# BSD 3-Clause License
#
# Copyright (c) 2026 <Sungwoo Jung, Cheng-Yu Tsai, Amaan Rahman, Junsik Yoon, Sandra Maria Shaji, Sung Kyu Lim >, University of Southern California
#
# Redistribution and use in source and binary forms, with or without
# modification, are permitted under the BSD 3-Clause License.
# See the LICENSE file in the project root for full license terms.


VERSION 5.8 ;
BUSBITCHARS "[]" ;
DIVIDERCHAR "/" ;

UNITS
  DATABASE MICRONS 10000 ;
END UNITS

MANUFACTURINGGRID 0.0001 ;

PROPERTYDEFINITIONS
  MACRO snapMode STRING ;
  MACRO segSnapMode STRING ;
  MACRO dimmingIntensity INTEGER ;
  MACRO arrayDisplay STRING ;
  MACRO displayResolution STRING ;
  MACRO instanceDrawingMode STRING ;
  MACRO autoZoomScale INTEGER ;
  MACRO filterSizeDrawingStyle STRING ;
  MACRO dimmingScope STRING ;
  MACRO filterSize REAL ;
  MACRO scrollPercent INTEGER ;
  MACRO gridMultiple INTEGER ;
  MACRO gridSpacing REAL ;
  MACRO xSnapSpacing REAL ;
  MACRO instLabel STRING ;
  MACRO autoZoomMode STRING ;
  MACRO lppVisibilityMode STRING ;
  MACRO stopLevel INTEGER ;
  MACRO mergeScope STRING ;
  MACRO ySnapSpacing REAL ;
  MACRO startLevel INTEGER ;
  MACRO pathCL STRING ;
END PROPERTYDEFINITIONS

LAYER well
  TYPE MASTERSLICE ;
END well

LAYER Gate
  TYPE MASTERSLICE ;
END Gate

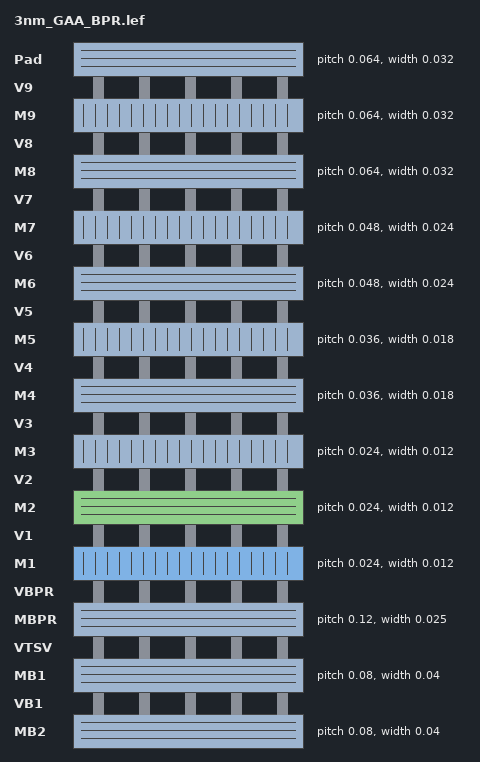
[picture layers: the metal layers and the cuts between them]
LAYER MB2
  TYPE ROUTING ;
  DIRECTION HORIZONTAL ;
  PITCH 0.08 ;
  WIDTH 0.04 ;
  PROPERTY LEF58_WIDTH "WIDTH 0.04 WRONGDIRECTION ;" ;
END MB2

LAYER VB1
  TYPE CUT ;
END VB1

LAYER MB1
  TYPE ROUTING ;
  DIRECTION HORIZONTAL ;
  PITCH 0.08 ;
  WIDTH 0.04 ;
  PROPERTY LEF58_WIDTH "WIDTH 0.04 WRONGDIRECTION ;" ;
END MB1

LAYER VTSV
  TYPE CUT ;
END VTSV

LAYER MBPR
  TYPE ROUTING ;
  DIRECTION HORIZONTAL ;
  PITCH 0.12 ;
  WIDTH 0.025 ;
  PROPERTY LEF58_WIDTH "WIDTH 0.025 WRONGDIRECTION ;" ;
END MBPR

LAYER VBPR
  TYPE CUT ;
END VBPR


LAYER M1
  TYPE ROUTING ;
  DIRECTION VERTICAL ;
  PITCH 0.024 ;
  WIDTH 0.012 ;
  PROPERTY LEF58_WIDTH "WIDTH 0.012 WRONGDIRECTION ;" ;
END M1

LAYER V1
  TYPE CUT ;
END V1

LAYER M2
  TYPE ROUTING ;
  DIRECTION HORIZONTAL ;
  PITCH 0.024 ;
  WIDTH 0.012 ;
  PROPERTY LEF58_WIDTH "WIDTH 0.012 WRONGDIRECTION ;" ;
END M2

LAYER V2
  TYPE CUT ;
END V2

LAYER M3
  TYPE ROUTING ;
  DIRECTION VERTICAL ;
  PITCH 0.024 ;
  WIDTH 0.012 ;
  PROPERTY LEF58_WIDTH "WIDTH 0.012 WRONGDIRECTION ;" ;
END M3

LAYER V3
  TYPE CUT ;
END V3

LAYER M4
  TYPE ROUTING ;
  DIRECTION HORIZONTAL ;
  PITCH 0.036 ;
  WIDTH 0.018 ;
  PROPERTY LEF58_WIDTH "WIDTH 0.018 WRONGDIRECTION ;" ;
END M4

LAYER V4
  TYPE CUT ;
END V4

LAYER M5
  TYPE ROUTING ;
  DIRECTION VERTICAL ;
  PITCH 0.036 ;
  WIDTH 0.018 ;
  PROPERTY LEF58_WIDTH "WIDTH 0.018 WRONGDIRECTION ;" ;
END M5

LAYER V5
  TYPE CUT ;
END V5

LAYER M6
  TYPE ROUTING ;
  DIRECTION HORIZONTAL ;
  PITCH 0.048 ;
  WIDTH 0.024 ;
  PROPERTY LEF58_WIDTH "WIDTH 0.024 WRONGDIRECTION ;" ;
END M6

LAYER V6
  TYPE CUT ;
END V6

LAYER M7
  TYPE ROUTING ;
  DIRECTION VERTICAL ;
  PITCH 0.048 ;
  WIDTH 0.024 ;
  PROPERTY LEF58_WIDTH "WIDTH 0.024 WRONGDIRECTION ;" ;
END M7

LAYER V7
  TYPE CUT ;
END V7

LAYER M8
  TYPE ROUTING ;
  DIRECTION HORIZONTAL ;
  PITCH 0.064 ;
  WIDTH 0.032 ;
  PROPERTY LEF58_WIDTH "WIDTH 0.032 WRONGDIRECTION ;" ;
END M8

LAYER V8
  TYPE CUT ;
END V8

LAYER M9
  TYPE ROUTING ;
  DIRECTION VERTICAL ;
  PITCH 0.064 ;
  WIDTH 0.032 ;
  PROPERTY LEF58_WIDTH "WIDTH 0.032 WRONGDIRECTION ;" ;
END M9

LAYER V9
  TYPE CUT ;
END V9

LAYER Pad
  TYPE ROUTING ;
  DIRECTION HORIZONTAL ;
  PITCH 0.064 ;
  WIDTH 0.032 ;
  PROPERTY LEF58_WIDTH "WIDTH 0.032 WRONGDIRECTION ;" ;
END Pad

LAYER Active
  TYPE MASTERSLICE ;
END Active

LAYER fin
  TYPE MASTERSLICE ;
END fin

LAYER P_SUB
  TYPE MASTERSLICE ;
END P_SUB

LAYER Dummy
  TYPE MASTERSLICE ;
END Dummy

LAYER GCut
  TYPE MASTERSLICE ;
END GCut

LAYER Nselect
  TYPE MASTERSLICE ;
END Nselect

LAYER Pselect
  TYPE MASTERSLICE ;
END Pselect

LAYER SDT
  TYPE MASTERSLICE ;
END SDT

LAYER LIG
  TYPE MASTERSLICE ;
END LIG

LAYER LISD
  TYPE MASTERSLICE ;
END LISD

LAYER V0
  TYPE MASTERSLICE ;
END V0

LAYER SLVT
  TYPE MASTERSLICE ;
END SLVT

LAYER LVT
  TYPE MASTERSLICE ;
END LVT

LAYER SRAMDRC
  TYPE MASTERSLICE ;
END SRAMDRC

LAYER BOUNDARY
  TYPE MASTERSLICE ;
END BOUNDARY

LAYER TEXT
  TYPE MASTERSLICE ;
END TEXT

LAYER SRAMVT
  TYPE MASTERSLICE ;
END SRAMVT

LAYER text
  TYPE MASTERSLICE ;
END text



#SITE coreSite
#  CLASS CORE ;
#  SIZE 0.042 BY 0.144 ;
#END core

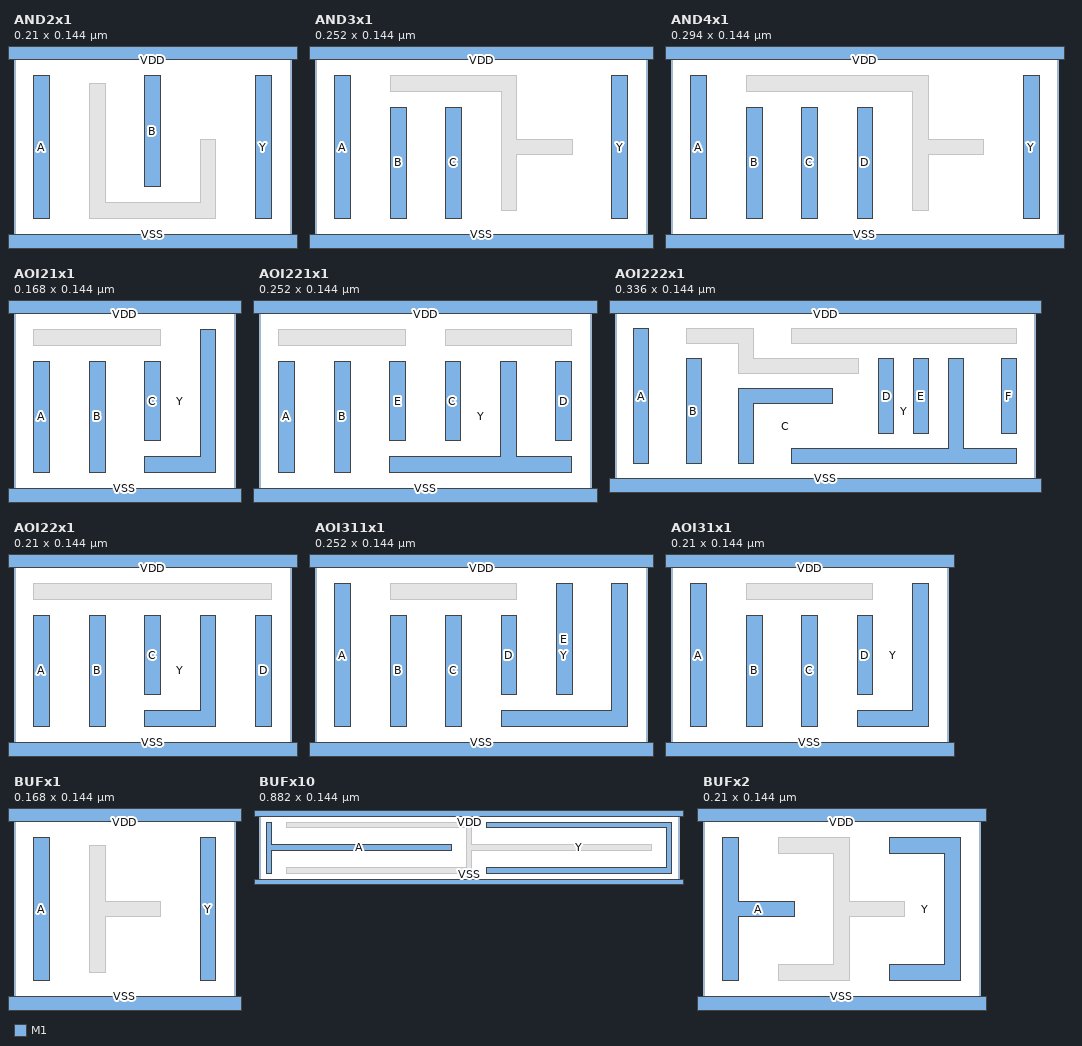
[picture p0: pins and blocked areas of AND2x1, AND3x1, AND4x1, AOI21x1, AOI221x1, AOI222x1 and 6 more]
MACRO AND2x1
  CLASS CORE ;
  FOREIGN AND2x1 ;
  ORIGIN 0 0 ;
  SIZE 0.21 BY 0.144 ;
  SYMMETRY X Y ;
  SITE coreSite ;
  PIN A
    DIRECTION INPUT ;
    USE SIGNAL ;
    PORT
      LAYER M1 ;
        RECT 0.0150 0.0180 0.0270 0.1260 ;
    END
  END A
  PIN B
    DIRECTION INPUT ;
    USE SIGNAL ;
    PORT
      LAYER M1 ;
        RECT 0.0990 0.0420 0.1110 0.1260 ;
    END
  END B
  PIN Y
    DIRECTION OUTPUT ;
    USE SIGNAL ;
    PORT
      LAYER M1 ;
        RECT 0.1830 0.0180 0.1950 0.1260 ;
    END
  END Y
  PIN VDD
    DIRECTION INOUT ;
    USE POWER ;
    PORT
      LAYER M1 ;
        RECT -0.0090 0.1380 0.2190 0.1500 ;
    END
  END VDD
  PIN VSS
    DIRECTION INOUT ;
    USE GROUND ;
    PORT
      LAYER M1 ;
        RECT -0.0090 -0.0060 0.2190 0.0060 ;
    END
  END VSS
  OBS
    LAYER M1 ;
      POLYGON 0.0690 0.1200 0.0690 0.0300 0.1410 0.0300 0.1410 0.0780 0.1530 0.0780 0.1530 0.0180 0.0570 0.0180 0.0570 0.1200 ;
  END
END AND2x1

MACRO AND3x1
  CLASS CORE ;
  FOREIGN AND3x1 ;
  ORIGIN 0 0 ;
  SIZE 0.252 BY 0.144 ;
  SYMMETRY X Y ;
  SITE coreSite ;
  PIN A
    DIRECTION INPUT ;
    USE SIGNAL ;
    PORT
      LAYER M1 ;
        RECT 0.0150 0.0180 0.0270 0.1260 ;
    END
  END A
  PIN B
    DIRECTION INPUT ;
    USE SIGNAL ;
    PORT
      LAYER M1 ;
        RECT 0.0570 0.0180 0.0690 0.1020 ;
    END
  END B
  PIN C
    DIRECTION INPUT ;
    USE SIGNAL ;
    PORT
      LAYER M1 ;
        RECT 0.0990 0.0180 0.1110 0.1020 ;
    END
  END C
  PIN Y
    DIRECTION OUTPUT ;
    USE SIGNAL ;
    PORT
      LAYER M1 ;
        RECT 0.2250 0.0180 0.2370 0.1260 ;
    END
  END Y
  PIN VDD
    DIRECTION INOUT ;
    USE POWER ;
    PORT
      LAYER M1 ;
        RECT -0.0090 0.1380 0.2610 0.1500 ;
    END
  END VDD
  PIN VSS
    DIRECTION INOUT ;
    USE GROUND ;
    PORT
      LAYER M1 ;
        RECT -0.0090 -0.0060 0.2610 0.0060 ;
    END
  END VSS
  OBS
    LAYER M1 ;
      POLYGON 0.1530 0.1260 0.1530 0.0780 0.1950 0.0780 0.1950 0.0660 0.1530 0.0660 0.1530 0.0240 0.1410 0.0240 0.1410 0.1140 0.0570 0.1140 0.0570 0.1260 ;
  END
END AND3x1

MACRO AND4x1
  CLASS CORE ;
  FOREIGN AND4x1 ;
  ORIGIN 0 0 ;
  SIZE 0.294 BY 0.144 ;
  SYMMETRY X Y ;
  SITE coreSite ;
  PIN A
    DIRECTION INPUT ;
    USE SIGNAL ;
    PORT
      LAYER M1 ;
        RECT 0.0150 0.0180 0.0270 0.1260 ;
    END
  END A
  PIN B
    DIRECTION INPUT ;
    USE SIGNAL ;
    PORT
      LAYER M1 ;
        RECT 0.0570 0.0180 0.0690 0.1020 ;
    END
  END B
  PIN C
    DIRECTION INPUT ;
    USE SIGNAL ;
    PORT
      LAYER M1 ;
        RECT 0.0990 0.0180 0.1110 0.1020 ;
    END
  END C
  PIN D
    DIRECTION INPUT ;
    USE SIGNAL ;
    PORT
      LAYER M1 ;
        RECT 0.1410 0.0180 0.1530 0.1020 ;
    END
  END D
  PIN Y
    DIRECTION OUTPUT ;
    USE SIGNAL ;
    PORT
      LAYER M1 ;
        RECT 0.2670 0.0180 0.2790 0.1260 ;
    END
  END Y
  PIN VDD
    DIRECTION INOUT ;
    USE POWER ;
    PORT
      LAYER M1 ;
        RECT -0.0090 0.1380 0.3030 0.1500 ;
    END
  END VDD
  PIN VSS
    DIRECTION INOUT ;
    USE GROUND ;
    PORT
      LAYER M1 ;
        RECT -0.0090 -0.0060 0.3030 0.0060 ;
    END
  END VSS
  OBS
    LAYER M1 ;
      POLYGON 0.1950 0.1260 0.1950 0.0780 0.2370 0.0780 0.2370 0.0660 0.1950 0.0660 0.1950 0.0240 0.1830 0.0240 0.1830 0.1140 0.0570 0.1140 0.0570 0.1260 ;
  END
END AND4x1

MACRO AOI21x1
  CLASS CORE ;
  FOREIGN AOI21x1 ;
  ORIGIN 0 0 ;
  SIZE 0.168 BY 0.144 ;
  SYMMETRY X Y ;
  SITE coreSite ;
  PIN A
    DIRECTION INPUT ;
    USE SIGNAL ;
    PORT
      LAYER M1 ;
        RECT 0.0150 0.0180 0.0270 0.1020 ;
    END
  END A
  PIN B
    DIRECTION INPUT ;
    USE SIGNAL ;
    PORT
      LAYER M1 ;
        RECT 0.0570 0.0180 0.0690 0.1020 ;
    END
  END B
  PIN C
    DIRECTION INPUT ;
    USE SIGNAL ;
    PORT
      LAYER M1 ;
        RECT 0.0990 0.0420 0.1110 0.1020 ;
    END
  END C
  PIN Y
    DIRECTION OUTPUT ;
    USE SIGNAL ;
    PORT
      LAYER M1 ;
        POLYGON 0.1530 0.1260 0.1530 0.0180 0.0990 0.0180 0.0990 0.0300 0.1410 0.0300 0.1410 0.1260 ;
    END
  END Y
  PIN VDD
    DIRECTION INOUT ;
    USE POWER ;
    PORT
      LAYER M1 ;
        RECT -0.0090 0.1380 0.1770 0.1500 ;
    END
  END VDD
  PIN VSS
    DIRECTION INOUT ;
    USE GROUND ;
    PORT
      LAYER M1 ;
        RECT -0.0090 -0.0060 0.1770 0.0060 ;
    END
  END VSS
  OBS
    LAYER M1 ;
      RECT 0.0150 0.1140 0.1110 0.1260 ;
  END
END AOI21x1

MACRO AOI221x1
  CLASS CORE ;
  FOREIGN AOI221x1 ;
  ORIGIN 0 0 ;
  SIZE 0.252 BY 0.144 ;
  SYMMETRY X Y ;
  SITE coreSite ;
  PIN A
    DIRECTION INPUT ;
    USE SIGNAL ;
    PORT
      LAYER M1 ;
        RECT 0.0150 0.0180 0.0270 0.1020 ;
    END
  END A
  PIN B
    DIRECTION INPUT ;
    USE SIGNAL ;
    PORT
      LAYER M1 ;
        RECT 0.0570 0.0180 0.0690 0.1020 ;
    END
  END B
  PIN C
    DIRECTION INPUT ;
    USE SIGNAL ;
    PORT
      LAYER M1 ;
        RECT 0.1410 0.0420 0.1530 0.1020 ;
    END
  END C
  PIN D
    DIRECTION INPUT ;
    USE SIGNAL ;
    PORT
      LAYER M1 ;
        RECT 0.2250 0.0420 0.2370 0.1020 ;
    END
  END D
  PIN E
    DIRECTION INPUT ;
    USE SIGNAL ;
    PORT
      LAYER M1 ;
        RECT 0.0990 0.0420 0.1110 0.1020 ;
    END
  END E
  PIN Y
    DIRECTION OUTPUT ;
    USE SIGNAL ;
    PORT
      LAYER M1 ;
        POLYGON 0.1950 0.1020 0.1950 0.0300 0.2370 0.0300 0.2370 0.0180 0.0990 0.0180 0.0990 0.0300 0.1830 0.0300 0.1830 0.1020 ;
    END
  END Y
  PIN VDD
    DIRECTION INOUT ;
    USE POWER ;
    PORT
      LAYER M1 ;
        RECT -0.0090 0.1380 0.2610 0.1500 ;
    END
  END VDD
  PIN VSS
    DIRECTION INOUT ;
    USE GROUND ;
    PORT
      LAYER M1 ;
        RECT -0.0090 -0.0060 0.2610 0.0060 ;
    END
  END VSS
  OBS
    LAYER M1 ;
      RECT 0.1410 0.1140 0.2370 0.1260 ;
      RECT 0.0150 0.1140 0.1110 0.1260 ;
  END
END AOI221x1

MACRO AOI222x1
  CLASS CORE ;
  FOREIGN AOI222x1 ;
  ORIGIN 0 0 ;
  SIZE 0.336 BY 0.144 ;
  SYMMETRY X Y ;
  SITE coreSite ;
  PIN A
    DIRECTION INPUT ;
    USE SIGNAL ;
    PORT
      LAYER M1 ;
        RECT 0.0150 0.0180 0.0270 0.1260 ;
    END
  END A
  PIN B
    DIRECTION INPUT ;
    USE SIGNAL ;
    PORT
      LAYER M1 ;
        RECT 0.0570 0.0180 0.0690 0.1020 ;
    END
  END B
  PIN C
    DIRECTION INPUT ;
    USE SIGNAL ;
    PORT
      LAYER M1 ;
        POLYGON 0.1740 0.0780 0.1740 0.0660 0.1110 0.0660 0.1110 0.0180 0.0990 0.0180 0.0990 0.0780 ;
    END
  END C
  PIN D
    DIRECTION INPUT ;
    USE SIGNAL ;
    PORT
      LAYER M1 ;
        RECT 0.2110 0.0420 0.2230 0.1020 ;
    END
  END D
  PIN E
    DIRECTION INPUT ;
    USE SIGNAL ;
    PORT
      LAYER M1 ;
        RECT 0.2390 0.0420 0.2510 0.1020 ;
    END
  END E
  PIN F
    DIRECTION INPUT ;
    USE SIGNAL ;
    PORT
      LAYER M1 ;
        RECT 0.3090 0.0420 0.3210 0.1020 ;
    END
  END F
  PIN Y
    DIRECTION OUTPUT ;
    USE SIGNAL ;
    PORT
      LAYER M1 ;
        POLYGON 0.2790 0.1020 0.2790 0.0300 0.3210 0.0300 0.3210 0.0180 0.1410 0.0180 0.1410 0.0300 0.2670 0.0300 0.2670 0.1020 ;
    END
  END Y
  PIN VDD
    DIRECTION INOUT ;
    USE POWER ;
    PORT
      LAYER M1 ;
        RECT -0.0090 0.1380 0.3450 0.1500 ;
    END
  END VDD
  PIN VSS
    DIRECTION INOUT ;
    USE GROUND ;
    PORT
      LAYER M1 ;
        RECT -0.0090 -0.0060 0.3450 0.0060 ;
    END
  END VSS
  OBS
    LAYER M1 ;
      RECT 0.1410 0.1140 0.3210 0.1260 ;
      POLYGON 0.1110 0.1260 0.1110 0.1020 0.1950 0.1020 0.1950 0.0900 0.0990 0.0900 0.0990 0.1140 0.0570 0.1140 0.0570 0.1260 ;
  END
END AOI222x1

MACRO AOI22x1
  CLASS CORE ;
  FOREIGN AOI22x1 ;
  ORIGIN 0 0 ;
  SIZE 0.21 BY 0.144 ;
  SYMMETRY X Y ;
  SITE coreSite ;
  PIN A
    DIRECTION INPUT ;
    USE SIGNAL ;
    PORT
      LAYER M1 ;
        RECT 0.0150 0.0180 0.0270 0.1020 ;
    END
  END A
  PIN B
    DIRECTION INPUT ;
    USE SIGNAL ;
    PORT
      LAYER M1 ;
        RECT 0.0570 0.0180 0.0690 0.1020 ;
    END
  END B
  PIN C
    DIRECTION INPUT ;
    USE SIGNAL ;
    PORT
      LAYER M1 ;
        RECT 0.0990 0.0420 0.1110 0.1020 ;
    END
  END C
  PIN D
    DIRECTION INPUT ;
    USE SIGNAL ;
    PORT
      LAYER M1 ;
        RECT 0.1830 0.0180 0.1950 0.1020 ;
    END
  END D
  PIN Y
    DIRECTION OUTPUT ;
    USE SIGNAL ;
    PORT
      LAYER M1 ;
        POLYGON 0.1530 0.1020 0.1530 0.0180 0.0990 0.0180 0.0990 0.0300 0.1410 0.0300 0.1410 0.1020 ;
    END
  END Y
  PIN VDD
    DIRECTION INOUT ;
    USE POWER ;
    PORT
      LAYER M1 ;
        RECT -0.0090 0.1380 0.2190 0.1500 ;
    END
  END VDD
  PIN VSS
    DIRECTION INOUT ;
    USE GROUND ;
    PORT
      LAYER M1 ;
        RECT -0.0090 -0.0060 0.2190 0.0060 ;
    END
  END VSS
  OBS
    LAYER M1 ;
      RECT 0.0150 0.1140 0.1950 0.1260 ;
  END
END AOI22x1

MACRO AOI311x1
  CLASS CORE ;
  FOREIGN AOI311x1 ;
  ORIGIN 0 0 ;
  SIZE 0.252 BY 0.144 ;
  SYMMETRY X Y ;
  SITE coreSite ;
  PIN A
    DIRECTION INPUT ;
    USE SIGNAL ;
    PORT
      LAYER M1 ;
        RECT 0.0150 0.0180 0.0270 0.1260 ;
    END
  END A
  PIN B
    DIRECTION INPUT ;
    USE SIGNAL ;
    PORT
      LAYER M1 ;
        RECT 0.0570 0.0180 0.0690 0.1020 ;
    END
  END B
  PIN C
    DIRECTION INPUT ;
    USE SIGNAL ;
    PORT
      LAYER M1 ;
        RECT 0.0990 0.0180 0.1110 0.1020 ;
    END
  END C
  PIN D
    DIRECTION INPUT ;
    USE SIGNAL ;
    PORT
      LAYER M1 ;
        RECT 0.1410 0.0420 0.1530 0.1020 ;
    END
  END D
  PIN E
    DIRECTION INPUT ;
    USE SIGNAL ;
    PORT
      LAYER M1 ;
        RECT 0.1830 0.0420 0.1950 0.1260 ;
    END
  END E
  PIN Y
    DIRECTION OUTPUT ;
    USE SIGNAL ;
    PORT
      LAYER M1 ;
        POLYGON 0.2370 0.1260 0.2370 0.0180 0.1410 0.0180 0.1410 0.0300 0.2250 0.0300 0.2250 0.1260 ;
    END
  END Y
  PIN VDD
    DIRECTION INOUT ;
    USE POWER ;
    PORT
      LAYER M1 ;
        RECT -0.0090 0.1380 0.2610 0.1500 ;
    END
  END VDD
  PIN VSS
    DIRECTION INOUT ;
    USE GROUND ;
    PORT
      LAYER M1 ;
        RECT -0.0090 -0.0060 0.2610 0.0060 ;
    END
  END VSS
  OBS
    LAYER M1 ;
      RECT 0.0570 0.1140 0.1530 0.1260 ;
  END
END AOI311x1

MACRO AOI31x1
  CLASS CORE ;
  FOREIGN AOI31x1 ;
  ORIGIN 0 0 ;
  SIZE 0.21 BY 0.144 ;
  SYMMETRY X Y ;
  SITE coreSite ;
  PIN A
    DIRECTION INPUT ;
    USE SIGNAL ;
    PORT
      LAYER M1 ;
        RECT 0.0150 0.0180 0.0270 0.1260 ;
    END
  END A
  PIN B
    DIRECTION INPUT ;
    USE SIGNAL ;
    PORT
      LAYER M1 ;
        RECT 0.0570 0.0180 0.0690 0.1020 ;
    END
  END B
  PIN C
    DIRECTION INPUT ;
    USE SIGNAL ;
    PORT
      LAYER M1 ;
        RECT 0.0990 0.0180 0.1110 0.1020 ;
    END
  END C
  PIN D
    DIRECTION INPUT ;
    USE SIGNAL ;
    PORT
      LAYER M1 ;
        RECT 0.1410 0.0420 0.1530 0.1020 ;
    END
  END D
  PIN Y
    DIRECTION OUTPUT ;
    USE SIGNAL ;
    PORT
      LAYER M1 ;
        POLYGON 0.1950 0.1260 0.1950 0.0180 0.1410 0.0180 0.1410 0.0300 0.1830 0.0300 0.1830 0.1260 ;
    END
  END Y
  PIN VDD
    DIRECTION INOUT ;
    USE POWER ;
    PORT
      LAYER M1 ;
        RECT -0.0090 0.1380 0.2190 0.1500 ;
    END
  END VDD
  PIN VSS
    DIRECTION INOUT ;
    USE GROUND ;
    PORT
      LAYER M1 ;
        RECT -0.0090 -0.0060 0.2190 0.0060 ;
    END
  END VSS
  OBS
    LAYER M1 ;
      RECT 0.0570 0.1140 0.1530 0.1260 ;
  END
END AOI31x1

MACRO BUFx1
  CLASS CORE ;
  FOREIGN BUFx1 ;
  ORIGIN 0 0 ;
  SIZE 0.168 BY 0.144 ;
  SYMMETRY X Y ;
  SITE coreSite ;
  PIN A
    DIRECTION INPUT ;
    USE SIGNAL ;
    PORT
      LAYER M1 ;
        RECT 0.0150 0.0180 0.0270 0.1260 ;
    END
  END A
  PIN Y
    DIRECTION OUTPUT ;
    USE SIGNAL ;
    PORT
      LAYER M1 ;
        RECT 0.1410 0.0180 0.1530 0.1260 ;
    END
  END Y
  PIN VDD
    DIRECTION INOUT ;
    USE POWER ;
    PORT
      LAYER M1 ;
        RECT -0.0090 0.1380 0.1770 0.1500 ;
    END
  END VDD
  PIN VSS
    DIRECTION INOUT ;
    USE GROUND ;
    PORT
      LAYER M1 ;
        RECT -0.0090 -0.0060 0.1770 0.0060 ;
    END
  END VSS
  OBS
    LAYER M1 ;
      POLYGON 0.0690 0.1200 0.0690 0.0780 0.1110 0.0780 0.1110 0.0660 0.0690 0.0660 0.0690 0.0240 0.0570 0.0240 0.0570 0.1200 ;
  END
END BUFx1

MACRO BUFx10
  CLASS CORE ;
  FOREIGN BUFx10 ;
  ORIGIN 0 0 ;
  SIZE 0.882 BY 0.144 ;
  SYMMETRY X Y ;
  SITE coreSite ;
  PIN A
    DIRECTION INPUT ;
    USE SIGNAL ;
    PORT
      LAYER M1 ;
        POLYGON 0.0270 0.1260 0.0270 0.0780 0.4050 0.0780 0.4050 0.0660 0.0270 0.0660 0.0270 0.0180 0.0150 0.0180 0.0150 0.1260 ;
    END
  END A
  PIN Y
    DIRECTION OUTPUT ;
    USE SIGNAL ;
    PORT
      LAYER M1 ;
        POLYGON 0.8670 0.1260 0.8670 0.0180 0.4770 0.0180 0.4770 0.0300 0.8550 0.0300 0.8550 0.1140 0.4770 0.1140 0.4770 0.1260 ;
    END
  END Y
  PIN VDD
    DIRECTION INOUT ;
    USE POWER ;
    PORT
      LAYER M1 ;
        RECT -0.0090 0.1380 0.8910 0.1500 ;
    END
  END VDD
  PIN VSS
    DIRECTION INOUT ;
    USE GROUND ;
    PORT
      LAYER M1 ;
        RECT -0.0090 -0.0060 0.8910 0.0060 ;
    END
  END VSS
  OBS
    LAYER M1 ;
      POLYGON 0.4470 0.1260 0.4470 0.0780 0.8250 0.0780 0.8250 0.0660 0.4470 0.0660 0.4470 0.0180 0.0570 0.0180 0.0570 0.0300 0.4350 0.0300 0.4350 0.1140 0.0570 0.1140 0.0570 0.1260 ;
  END
  PROPERTY stopLevel 0 ;
  PROPERTY startLevel 0 ;
  PROPERTY snapMode "orthogonal" ;
  PROPERTY segSnapMode "orthogonal" ;
  PROPERTY pathCL "yes" ;
  PROPERTY lppVisibilityMode "donotCheckValidity" ;
  PROPERTY instanceDrawingMode "BBox" ;
  PROPERTY autoZoomScale 90 ;
  PROPERTY gridSpacing 1 ;
  PROPERTY xSnapSpacing 0.001 ;
  PROPERTY autoZoomMode "Pan" ;
  PROPERTY mergeScope "pcells" ;
  PROPERTY gridMultiple 5 ;
  PROPERTY arrayDisplay "Full" ;
  PROPERTY scrollPercent 25 ;
  PROPERTY displayResolution "Medium" ;
  PROPERTY instLabel "master" ;
  PROPERTY ySnapSpacing 0.001 ;
  PROPERTY filterSize 6 ;
  PROPERTY dimmingIntensity 50 ;
  PROPERTY filterSizeDrawingStyle "empty" ;
  PROPERTY dimmingScope "none" ;
END BUFx10

MACRO BUFx2
  CLASS CORE ;
  FOREIGN BUFx2 ;
  ORIGIN 0 0 ;
  SIZE 0.21 BY 0.144 ;
  SYMMETRY X Y ;
  SITE coreSite ;
  PIN A
    DIRECTION INPUT ;
    USE SIGNAL ;
    PORT
      LAYER M1 ;
        POLYGON 0.0270 0.1260 0.0270 0.0780 0.0690 0.0780 0.0690 0.0660 0.0270 0.0660 0.0270 0.0180 0.0150 0.0180 0.0150 0.1260 ;
    END
  END A
  PIN Y
    DIRECTION OUTPUT ;
    USE SIGNAL ;
    PORT
      LAYER M1 ;
        POLYGON 0.1950 0.1260 0.1950 0.0180 0.1410 0.0180 0.1410 0.0300 0.1830 0.0300 0.1830 0.1140 0.1410 0.1140 0.1410 0.1260 ;
    END
  END Y
  PIN VDD
    DIRECTION INOUT ;
    USE POWER ;
    PORT
      LAYER M1 ;
        RECT -0.0090 0.1380 0.2190 0.1500 ;
    END
  END VDD
  PIN VSS
    DIRECTION INOUT ;
    USE GROUND ;
    PORT
      LAYER M1 ;
        RECT -0.0090 -0.0060 0.2190 0.0060 ;
    END
  END VSS
  OBS
    LAYER M1 ;
      POLYGON 0.1110 0.1260 0.1110 0.0780 0.1530 0.0780 0.1530 0.0660 0.1110 0.0660 0.1110 0.0180 0.0570 0.0180 0.0570 0.0300 0.0990 0.0300 0.0990 0.1140 0.0570 0.1140 0.0570 0.1260 ;
  END
END BUFx2

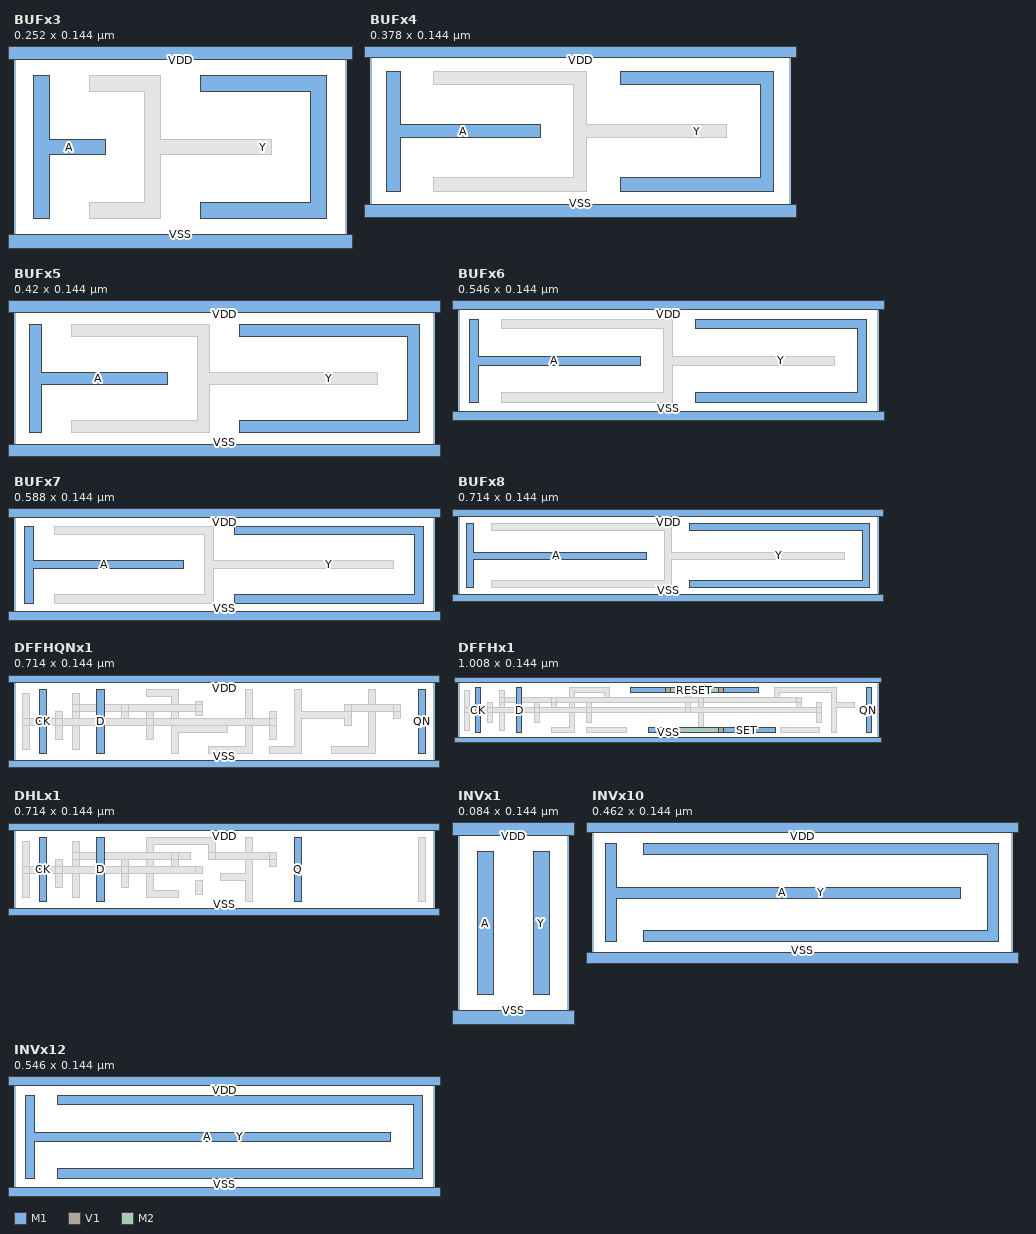
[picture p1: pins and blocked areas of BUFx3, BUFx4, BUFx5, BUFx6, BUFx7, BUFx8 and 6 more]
MACRO BUFx3
  CLASS CORE ;
  FOREIGN BUFx3 ;
  ORIGIN 0 0 ;
  SIZE 0.252 BY 0.144 ;
  SYMMETRY X Y ;
  SITE coreSite ;
  PIN A
    DIRECTION INPUT ;
    USE SIGNAL ;
    PORT
      LAYER M1 ;
        POLYGON 0.0270 0.1260 0.0270 0.0780 0.0690 0.0780 0.0690 0.0660 0.0270 0.0660 0.0270 0.0180 0.0150 0.0180 0.0150 0.1260 ;
    END
  END A
  PIN Y
    DIRECTION OUTPUT ;
    USE SIGNAL ;
    PORT
      LAYER M1 ;
        POLYGON 0.2370 0.1260 0.2370 0.0180 0.1410 0.0180 0.1410 0.0300 0.2250 0.0300 0.2250 0.1140 0.1410 0.1140 0.1410 0.1260 ;
    END
  END Y
  PIN VDD
    DIRECTION INOUT ;
    USE POWER ;
    PORT
      LAYER M1 ;
        RECT -0.0090 0.1380 0.2610 0.1500 ;
    END
  END VDD
  PIN VSS
    DIRECTION INOUT ;
    USE GROUND ;
    PORT
      LAYER M1 ;
        RECT -0.0090 -0.0060 0.2610 0.0060 ;
    END
  END VSS
  OBS
    LAYER M1 ;
      POLYGON 0.1110 0.1260 0.1110 0.0780 0.1950 0.0780 0.1950 0.0660 0.1110 0.0660 0.1110 0.0180 0.0570 0.0180 0.0570 0.0300 0.0990 0.0300 0.0990 0.1140 0.0570 0.1140 0.0570 0.1260 ;
  END
  PROPERTY stopLevel 0 ;
  PROPERTY startLevel 0 ;
  PROPERTY snapMode "orthogonal" ;
  PROPERTY segSnapMode "orthogonal" ;
  PROPERTY pathCL "yes" ;
  PROPERTY lppVisibilityMode "donotCheckValidity" ;
  PROPERTY instanceDrawingMode "BBox" ;
  PROPERTY autoZoomScale 90 ;
  PROPERTY gridSpacing 1 ;
  PROPERTY xSnapSpacing 0.001 ;
  PROPERTY autoZoomMode "Pan" ;
  PROPERTY mergeScope "pcells" ;
  PROPERTY gridMultiple 5 ;
  PROPERTY arrayDisplay "Full" ;
  PROPERTY scrollPercent 25 ;
  PROPERTY displayResolution "Medium" ;
  PROPERTY instLabel "master" ;
  PROPERTY ySnapSpacing 0.001 ;
  PROPERTY filterSize 6 ;
  PROPERTY dimmingIntensity 50 ;
  PROPERTY filterSizeDrawingStyle "empty" ;
  PROPERTY dimmingScope "none" ;
END BUFx3

MACRO BUFx4
  CLASS CORE ;
  FOREIGN BUFx4 ;
  ORIGIN 0 0 ;
  SIZE 0.378 BY 0.144 ;
  SYMMETRY X Y ;
  SITE coreSite ;
  PIN A
    DIRECTION INPUT ;
    USE SIGNAL ;
    PORT
      LAYER M1 ;
        POLYGON 0.0270 0.1260 0.0270 0.0780 0.1530 0.0780 0.1530 0.0660 0.0270 0.0660 0.0270 0.0180 0.0150 0.0180 0.0150 0.1260 ;
    END
  END A
  PIN Y
    DIRECTION OUTPUT ;
    USE SIGNAL ;
    PORT
      LAYER M1 ;
        POLYGON 0.3630 0.1260 0.3630 0.0180 0.2250 0.0180 0.2250 0.0300 0.3510 0.0300 0.3510 0.1140 0.2250 0.1140 0.2250 0.1260 ;
    END
  END Y
  PIN VDD
    DIRECTION INOUT ;
    USE POWER ;
    PORT
      LAYER M1 ;
        RECT -0.0090 0.1380 0.3870 0.1500 ;
    END
  END VDD
  PIN VSS
    DIRECTION INOUT ;
    USE GROUND ;
    PORT
      LAYER M1 ;
        RECT -0.0090 -0.0060 0.3870 0.0060 ;
    END
  END VSS
  OBS
    LAYER M1 ;
      POLYGON 0.1950 0.1260 0.1950 0.0780 0.3210 0.0780 0.3210 0.0660 0.1950 0.0660 0.1950 0.0180 0.0570 0.0180 0.0570 0.0300 0.1830 0.0300 0.1830 0.1140 0.0570 0.1140 0.0570 0.1260 ;
  END
  PROPERTY stopLevel 0 ;
  PROPERTY startLevel 0 ;
  PROPERTY snapMode "orthogonal" ;
  PROPERTY segSnapMode "orthogonal" ;
  PROPERTY pathCL "yes" ;
  PROPERTY lppVisibilityMode "donotCheckValidity" ;
  PROPERTY instanceDrawingMode "BBox" ;
  PROPERTY autoZoomScale 90 ;
  PROPERTY gridSpacing 1 ;
  PROPERTY xSnapSpacing 0.001 ;
  PROPERTY autoZoomMode "Pan" ;
  PROPERTY mergeScope "pcells" ;
  PROPERTY gridMultiple 5 ;
  PROPERTY arrayDisplay "Full" ;
  PROPERTY scrollPercent 25 ;
  PROPERTY displayResolution "Medium" ;
  PROPERTY instLabel "master" ;
  PROPERTY ySnapSpacing 0.001 ;
  PROPERTY filterSize 6 ;
  PROPERTY dimmingIntensity 50 ;
  PROPERTY filterSizeDrawingStyle "empty" ;
  PROPERTY dimmingScope "none" ;
END BUFx4

MACRO BUFx5
  CLASS CORE ;
  FOREIGN BUFx5 ;
  ORIGIN 0 0 ;
  SIZE 0.42 BY 0.144 ;
  SYMMETRY X Y ;
  SITE coreSite ;
  PIN A
    DIRECTION INPUT ;
    USE SIGNAL ;
    PORT
      LAYER M1 ;
        POLYGON 0.0270 0.1260 0.0270 0.0780 0.1530 0.0780 0.1530 0.0660 0.0270 0.0660 0.0270 0.0180 0.0150 0.0180 0.0150 0.1260 ;
    END
  END A
  PIN Y
    DIRECTION OUTPUT ;
    USE SIGNAL ;
    PORT
      LAYER M1 ;
        POLYGON 0.4050 0.1260 0.4050 0.0180 0.2250 0.0180 0.2250 0.0300 0.3930 0.0300 0.3930 0.1140 0.2250 0.1140 0.2250 0.1260 ;
    END
  END Y
  PIN VDD
    DIRECTION INOUT ;
    USE POWER ;
    PORT
      LAYER M1 ;
        RECT -0.0090 0.1380 0.4290 0.1500 ;
    END
  END VDD
  PIN VSS
    DIRECTION INOUT ;
    USE GROUND ;
    PORT
      LAYER M1 ;
        RECT -0.0090 -0.0060 0.4290 0.0060 ;
    END
  END VSS
  OBS
    LAYER M1 ;
      POLYGON 0.1950 0.1260 0.1950 0.0780 0.3630 0.0780 0.3630 0.0660 0.1950 0.0660 0.1950 0.0180 0.0570 0.0180 0.0570 0.0300 0.1830 0.0300 0.1830 0.1140 0.0570 0.1140 0.0570 0.1260 ;
  END
  PROPERTY stopLevel 0 ;
  PROPERTY startLevel 0 ;
  PROPERTY snapMode "orthogonal" ;
  PROPERTY segSnapMode "orthogonal" ;
  PROPERTY pathCL "yes" ;
  PROPERTY lppVisibilityMode "donotCheckValidity" ;
  PROPERTY instanceDrawingMode "BBox" ;
  PROPERTY autoZoomScale 90 ;
  PROPERTY gridSpacing 1 ;
  PROPERTY xSnapSpacing 0.001 ;
  PROPERTY autoZoomMode "Pan" ;
  PROPERTY mergeScope "pcells" ;
  PROPERTY gridMultiple 5 ;
  PROPERTY arrayDisplay "Full" ;
  PROPERTY scrollPercent 25 ;
  PROPERTY displayResolution "Medium" ;
  PROPERTY instLabel "master" ;
  PROPERTY ySnapSpacing 0.001 ;
  PROPERTY filterSize 6 ;
  PROPERTY dimmingIntensity 50 ;
  PROPERTY filterSizeDrawingStyle "empty" ;
  PROPERTY dimmingScope "none" ;
END BUFx5

MACRO BUFx6
  CLASS CORE ;
  FOREIGN BUFx6 ;
  ORIGIN 0 0 ;
  SIZE 0.546 BY 0.144 ;
  SYMMETRY X Y ;
  SITE coreSite ;
  PIN A
    DIRECTION INPUT ;
    USE SIGNAL ;
    PORT
      LAYER M1 ;
        POLYGON 0.0270 0.1260 0.0270 0.0780 0.2370 0.0780 0.2370 0.0660 0.0270 0.0660 0.0270 0.0180 0.0150 0.0180 0.0150 0.1260 ;
    END
  END A
  PIN Y
    DIRECTION OUTPUT ;
    USE SIGNAL ;
    PORT
      LAYER M1 ;
        POLYGON 0.5310 0.1260 0.5310 0.0180 0.3090 0.0180 0.3090 0.0300 0.5190 0.0300 0.5190 0.1140 0.3090 0.1140 0.3090 0.1260 ;
    END
  END Y
  PIN VDD
    DIRECTION INOUT ;
    USE POWER ;
    PORT
      LAYER M1 ;
        RECT -0.0090 0.1380 0.5550 0.1500 ;
    END
  END VDD
  PIN VSS
    DIRECTION INOUT ;
    USE GROUND ;
    PORT
      LAYER M1 ;
        RECT -0.0090 -0.0060 0.5550 0.0060 ;
    END
  END VSS
  OBS
    LAYER M1 ;
      POLYGON 0.2790 0.1260 0.2790 0.0780 0.4890 0.0780 0.4890 0.0660 0.2790 0.0660 0.2790 0.0180 0.0570 0.0180 0.0570 0.0300 0.2670 0.0300 0.2670 0.1140 0.0570 0.1140 0.0570 0.1260 ;
  END
  PROPERTY stopLevel 0 ;
  PROPERTY startLevel 0 ;
  PROPERTY snapMode "orthogonal" ;
  PROPERTY segSnapMode "orthogonal" ;
  PROPERTY pathCL "yes" ;
  PROPERTY lppVisibilityMode "donotCheckValidity" ;
  PROPERTY instanceDrawingMode "BBox" ;
  PROPERTY autoZoomScale 90 ;
  PROPERTY gridSpacing 1 ;
  PROPERTY xSnapSpacing 0.001 ;
  PROPERTY autoZoomMode "Pan" ;
  PROPERTY mergeScope "pcells" ;
  PROPERTY gridMultiple 5 ;
  PROPERTY arrayDisplay "Full" ;
  PROPERTY scrollPercent 25 ;
  PROPERTY displayResolution "Medium" ;
  PROPERTY instLabel "master" ;
  PROPERTY ySnapSpacing 0.001 ;
  PROPERTY filterSize 6 ;
  PROPERTY dimmingIntensity 50 ;
  PROPERTY filterSizeDrawingStyle "empty" ;
  PROPERTY dimmingScope "none" ;
END BUFx6

MACRO BUFx7
  CLASS CORE ;
  FOREIGN BUFx7 ;
  ORIGIN 0 0 ;
  SIZE 0.588 BY 0.144 ;
  SYMMETRY X Y ;
  SITE coreSite ;
  PIN A
    DIRECTION INPUT ;
    USE SIGNAL ;
    PORT
      LAYER M1 ;
        POLYGON 0.0270 0.1260 0.0270 0.0780 0.2370 0.0780 0.2370 0.0660 0.0270 0.0660 0.0270 0.0180 0.0150 0.0180 0.0150 0.1260 ;
    END
  END A
  PIN Y
    DIRECTION OUTPUT ;
    USE SIGNAL ;
    PORT
      LAYER M1 ;
        POLYGON 0.5730 0.1260 0.5730 0.0180 0.3090 0.0180 0.3090 0.0300 0.5610 0.0300 0.5610 0.1140 0.3090 0.1140 0.3090 0.1260 ;
    END
  END Y
  PIN VDD
    DIRECTION INOUT ;
    USE POWER ;
    PORT
      LAYER M1 ;
        RECT -0.0090 0.1380 0.5970 0.1500 ;
    END
  END VDD
  PIN VSS
    DIRECTION INOUT ;
    USE GROUND ;
    PORT
      LAYER M1 ;
        RECT -0.0090 -0.0060 0.5970 0.0060 ;
    END
  END VSS
  OBS
    LAYER M1 ;
      POLYGON 0.2790 0.1260 0.2790 0.0780 0.5310 0.0780 0.5310 0.0660 0.2790 0.0660 0.2790 0.0180 0.0570 0.0180 0.0570 0.0300 0.2670 0.0300 0.2670 0.1140 0.0570 0.1140 0.0570 0.1260 ;
  END
  PROPERTY stopLevel 0 ;
  PROPERTY startLevel 0 ;
  PROPERTY snapMode "orthogonal" ;
  PROPERTY segSnapMode "orthogonal" ;
  PROPERTY pathCL "yes" ;
  PROPERTY lppVisibilityMode "donotCheckValidity" ;
  PROPERTY instanceDrawingMode "BBox" ;
  PROPERTY autoZoomScale 90 ;
  PROPERTY gridSpacing 1 ;
  PROPERTY xSnapSpacing 0.001 ;
  PROPERTY autoZoomMode "Pan" ;
  PROPERTY mergeScope "pcells" ;
  PROPERTY gridMultiple 5 ;
  PROPERTY arrayDisplay "Full" ;
  PROPERTY scrollPercent 25 ;
  PROPERTY displayResolution "Medium" ;
  PROPERTY instLabel "master" ;
  PROPERTY ySnapSpacing 0.001 ;
  PROPERTY filterSize 6 ;
  PROPERTY dimmingIntensity 50 ;
  PROPERTY filterSizeDrawingStyle "empty" ;
  PROPERTY dimmingScope "none" ;
END BUFx7

MACRO BUFx8
  CLASS CORE ;
  FOREIGN BUFx8 ;
  ORIGIN 0 0 ;
  SIZE 0.714 BY 0.144 ;
  SYMMETRY X Y ;
  SITE coreSite ;
  PIN A
    DIRECTION INPUT ;
    USE SIGNAL ;
    PORT
      LAYER M1 ;
        POLYGON 0.0270 0.1260 0.0270 0.0780 0.3210 0.0780 0.3210 0.0660 0.0270 0.0660 0.0270 0.0180 0.0150 0.0180 0.0150 0.1260 ;
    END
  END A
  PIN Y
    DIRECTION OUTPUT ;
    USE SIGNAL ;
    PORT
      LAYER M1 ;
        POLYGON 0.6990 0.1260 0.6990 0.0180 0.3930 0.0180 0.3930 0.0300 0.6870 0.0300 0.6870 0.1140 0.3930 0.1140 0.3930 0.1260 ;
    END
  END Y
  PIN VDD
    DIRECTION INOUT ;
    USE POWER ;
    PORT
      LAYER M1 ;
        RECT -0.0090 0.1380 0.7230 0.1500 ;
    END
  END VDD
  PIN VSS
    DIRECTION INOUT ;
    USE GROUND ;
    PORT
      LAYER M1 ;
        RECT -0.0090 -0.0060 0.7230 0.0060 ;
    END
  END VSS
  OBS
    LAYER M1 ;
      POLYGON 0.3630 0.1260 0.3630 0.0780 0.6570 0.0780 0.6570 0.0660 0.3630 0.0660 0.3630 0.0180 0.0570 0.0180 0.0570 0.0300 0.3510 0.0300 0.3510 0.1140 0.0570 0.1140 0.0570 0.1260 ;
  END
  PROPERTY stopLevel 0 ;
  PROPERTY startLevel 0 ;
  PROPERTY snapMode "orthogonal" ;
  PROPERTY segSnapMode "orthogonal" ;
  PROPERTY pathCL "yes" ;
  PROPERTY lppVisibilityMode "donotCheckValidity" ;
  PROPERTY instanceDrawingMode "BBox" ;
  PROPERTY autoZoomScale 90 ;
  PROPERTY gridSpacing 1 ;
  PROPERTY xSnapSpacing 0.001 ;
  PROPERTY autoZoomMode "Pan" ;
  PROPERTY mergeScope "pcells" ;
  PROPERTY gridMultiple 5 ;
  PROPERTY arrayDisplay "Full" ;
  PROPERTY scrollPercent 25 ;
  PROPERTY displayResolution "Medium" ;
  PROPERTY instLabel "master" ;
  PROPERTY ySnapSpacing 0.001 ;
  PROPERTY filterSize 6 ;
  PROPERTY dimmingIntensity 50 ;
  PROPERTY filterSizeDrawingStyle "empty" ;
  PROPERTY dimmingScope "none" ;
END BUFx8

MACRO DFFHQNx1
  CLASS CORE ;
  FOREIGN DFFHQNx1 ;
  ORIGIN 0 0 ;
  SIZE 0.714 BY 0.144 ;
  SYMMETRY X Y ;
  SITE coreSite ;
  PIN D
    DIRECTION INPUT ;
    USE SIGNAL ;
    PORT
      LAYER M1 ;
        RECT 0.1410 0.0180 0.1530 0.1260 ;
    END
  END D
  PIN CK
    DIRECTION INPUT ;
    USE SIGNAL ;
    PORT
      LAYER M1 ;
        RECT 0.0430 0.0180 0.0550 0.1260 ;
    END
  END CK
  PIN QN
    DIRECTION OUTPUT ;
    USE SIGNAL ;
    PORT
      LAYER M1 ;
        RECT 0.6870 0.0180 0.6990 0.1260 ;
    END
  END QN
  PIN VDD
    DIRECTION INOUT ;
    USE POWER ;
    PORT
      LAYER M1 ;
        RECT -0.0090 0.1380 0.7230 0.1500 ;
    END
  END VDD
  PIN VSS
    DIRECTION INOUT ;
    USE GROUND ;
    PORT
      LAYER M1 ;
        RECT -0.0090 -0.0060 0.7230 0.0060 ;
    END
  END VSS
  OBS
    LAYER M1 ;
      POLYGON 0.6150 0.1260 0.6150 0.0180 0.5400 0.0180 0.5400 0.0300 0.6030 0.0300 0.6030 0.1260 ;
      POLYGON 0.4890 0.1260 0.4890 0.0900 0.5730 0.0900 0.5730 0.0660 0.5610 0.0660 0.5610 0.0780 0.4890 0.0780 0.4890 0.0180 0.4350 0.0180 0.4350 0.0300 0.4770 0.0300 0.4770 0.1260 ;
      POLYGON 0.4050 0.1260 0.4050 0.0180 0.3300 0.0180 0.3300 0.0300 0.3930 0.0300 0.3930 0.1260 ;
      POLYGON 0.2790 0.1260 0.2790 0.0660 0.3630 0.0660 0.3630 0.0540 0.2790 0.0540 0.2790 0.0180 0.2670 0.0180 0.2670 0.1140 0.2250 0.1140 0.2250 0.1260 ;
      RECT 0.0990 0.0240 0.1110 0.1200 ;
      RECT 0.0150 0.0240 0.0270 0.1200 ;
      RECT 0.3090 0.0830 0.3210 0.1070 ;
      RECT 0.6450 0.0780 0.6570 0.1020 ;
      RECT 0.1830 0.0780 0.1950 0.1020 ;
      RECT 0.4350 0.0420 0.4470 0.0900 ;
      RECT 0.2250 0.0420 0.2370 0.0900 ;
      RECT 0.0710 0.0420 0.0830 0.0900 ;
    LAYER M2 ;
      RECT 0.5610 0.0900 0.6570 0.1020 ;
      RECT 0.0990 0.0900 0.3210 0.1020 ;
      RECT 0.0150 0.0660 0.4470 0.0780 ;
    LAYER V1 ;
      RECT 0.6450 0.0900 0.6570 0.1020 ;
      RECT 0.5610 0.0900 0.5730 0.1020 ;
      RECT 0.3090 0.0900 0.3210 0.1020 ;
      RECT 0.1830 0.0900 0.1950 0.1020 ;
      RECT 0.0990 0.0900 0.1110 0.1020 ;
      RECT 0.4350 0.0660 0.4470 0.0780 ;
      RECT 0.2250 0.0660 0.2370 0.0780 ;
      RECT 0.0710 0.0660 0.0830 0.0780 ;
      RECT 0.0150 0.0660 0.0270 0.0780 ;
  END
END DFFHQNx1

MACRO DFFHx1
  CLASS CORE ;
  FOREIGN DFFHx1 ;
  ORIGIN 0 0 ;
  SIZE 1.008 BY 0.144 ;
  SYMMETRY X Y ;
  SITE coreSite ;
  PIN D
    DIRECTION INPUT ;
    USE SIGNAL ;
    PORT
      LAYER M1 ;
        RECT 0.1410 0.0180 0.1530 0.1260 ;
    END
  END D
  PIN CK
    DIRECTION INPUT ;
    USE SIGNAL ;
    PORT
      LAYER M1 ;
        RECT 0.0430 0.0180 0.0550 0.1260 ;
    END
  END CK
  PIN RESET
    DIRECTION INPUT ;
    USE SIGNAL ;
    PORT
      LAYER V1 ;
        RECT 0.4980 0.1140 0.5100 0.1260 ;
        RECT 0.6240 0.1140 0.6360 0.1260 ;
      LAYER M1 ;
        RECT 0.4140 0.1140 0.5100 0.1260 ;
        RECT 0.6240 0.1140 0.7200 0.1260 ;
      LAYER M2 ;
        RECT 0.4980 0.1140 0.6360 0.1260 ;
    END
  END RESET
  PIN SET
    DIRECTION INPUT ;
    USE SIGNAL ;
    PORT
      LAYER V1 ;
        RECT 0.4980 0.0180 0.5100 0.0300 ;
        RECT 0.6240 0.0180 0.6360 0.0300 ;
      LAYER M1 ;
        RECT 0.4560 0.0180 0.5100 0.0300 ;
        RECT 0.6240 0.0180 0.7620 0.0300 ;
      LAYER M2 ;
        RECT 0.4980 0.0180 0.6360 0.0300 ;
    END
  END SET
  PIN QN
    DIRECTION OUTPUT ;
    USE SIGNAL ;
    PORT
      LAYER M1 ;
        RECT 0.9810 0.0180 0.9930 0.1260 ;
    END
  END QN
  PIN VDD
    DIRECTION INOUT ;
    USE POWER ;
    PORT
      LAYER M1 ;
        RECT -0.0090 0.1380 1.0170 0.1500 ;
    END
  END VDD
  PIN VSS
    DIRECTION INOUT ;
    USE GROUND ;
    PORT
      LAYER M1 ;
        RECT -0.0090 -0.0060 1.0170 0.0060 ;
    END
  END VSS
  OBS
    LAYER M1 ;
      POLYGON 0.9090 0.1260 0.9090 0.0900 0.9510 0.0900 0.9510 0.0780 0.9090 0.0780 0.9090 0.0180 0.8970 0.0180 0.8970 0.1140 0.7720 0.1140 0.7720 0.0900 0.6060 0.0900 0.6060 0.1020 0.7600 0.1020 0.7600 0.1260 ;
      RECT 0.5460 0.0660 0.5580 0.1260 ;
      POLYGON 0.3630 0.1260 0.3630 0.1020 0.4890 0.1020 0.4890 0.0900 0.3510 0.0900 0.3510 0.1140 0.2790 0.1140 0.2790 0.0180 0.2250 0.0180 0.2250 0.0300 0.2670 0.0300 0.2670 0.1260 ;
      RECT 0.0990 0.0240 0.1110 0.1200 ;
      RECT 0.0150 0.0240 0.0270 0.1200 ;
      RECT 0.8130 0.0780 0.8250 0.1020 ;
      POLYGON 0.5880 0.1020 0.5880 0.0180 0.5460 0.0180 0.5460 0.0300 0.5760 0.0300 0.5760 0.1020 ;
      RECT 0.2250 0.0780 0.2370 0.1020 ;
      RECT 0.8600 0.0420 0.8720 0.0900 ;
      RECT 0.3090 0.0420 0.3210 0.0900 ;
      RECT 0.1830 0.0420 0.1950 0.0900 ;
      RECT 0.0710 0.0420 0.0830 0.0900 ;
      RECT 0.6450 0.0660 0.7830 0.0780 ;
      RECT 0.3720 0.0660 0.5280 0.0780 ;
      RECT 0.7740 0.0180 0.8670 0.0300 ;
      RECT 0.3090 0.0180 0.4050 0.0300 ;
    LAYER M2 ;
      RECT 0.0990 0.0900 0.8250 0.1020 ;
      RECT 0.0150 0.0660 0.8720 0.0780 ;
    LAYER V1 ;
      RECT 0.8130 0.0900 0.8250 0.1020 ;
      RECT 0.5760 0.0900 0.5880 0.1020 ;
      RECT 0.2250 0.0900 0.2370 0.1020 ;
      RECT 0.0990 0.0900 0.1110 0.1020 ;
      RECT 0.8600 0.0660 0.8720 0.0780 ;
      RECT 0.5460 0.0660 0.5580 0.0780 ;
      RECT 0.3090 0.0660 0.3210 0.0780 ;
      RECT 0.1830 0.0660 0.1950 0.0780 ;
      RECT 0.0710 0.0660 0.0830 0.0780 ;
      RECT 0.0150 0.0660 0.0270 0.0780 ;
  END
END DFFHx1

MACRO DHLx1
  CLASS CORE ;
  FOREIGN DHLx1 ;
  ORIGIN 0 0 ;
  SIZE 0.714 BY 0.144 ;
  SYMMETRY X Y ;
  SITE coreSite ;
  PIN CK
    DIRECTION INPUT ;
    USE SIGNAL ;
    PORT
      LAYER M1 ;
        RECT 0.0430 0.0180 0.0550 0.1260 ;
    END
  END CK
  PIN D
    DIRECTION INPUT ;
    USE SIGNAL ;
    PORT
      LAYER M1 ;
        RECT 0.1410 0.0180 0.1530 0.1260 ;
    END
  END D
  PIN Q
    DIRECTION OUTPUT ;
    USE SIGNAL ;
    PORT
      LAYER M1 ;
        RECT 0.4770 0.0180 0.4890 0.1260 ;
    END
  END Q
  PIN VDD
    DIRECTION INOUT ;
    USE POWER ;
    PORT
      LAYER M1 ;
        RECT -0.0090 0.1380 0.7230 0.1500 ;
    END
  END VDD
  PIN VSS
    DIRECTION INOUT ;
    USE GROUND ;
    PORT
      LAYER M1 ;
        RECT -0.0090 -0.0060 0.7230 0.0060 ;
    END
  END VSS
  OBS
    LAYER M1 ;
      RECT 0.6870 0.0180 0.6990 0.1260 ;
      POLYGON 0.4050 0.1260 0.4050 0.0180 0.3930 0.0180 0.3930 0.0540 0.3510 0.0540 0.3510 0.0660 0.3930 0.0660 0.3930 0.1260 ;
      POLYGON 0.3420 0.1260 0.3420 0.1020 0.3630 0.1020 0.3630 0.0900 0.3300 0.0900 0.3300 0.1140 0.2370 0.1140 0.2370 0.0360 0.2790 0.0360 0.2790 0.0240 0.2250 0.0240 0.2250 0.1260 ;
      RECT 0.0990 0.0240 0.1110 0.1200 ;
      RECT 0.0150 0.0240 0.0270 0.1200 ;
      RECT 0.4350 0.0780 0.4470 0.1020 ;
      POLYGON 0.3000 0.1020 0.3000 0.0900 0.2790 0.0900 0.2790 0.0780 0.2670 0.0780 0.2670 0.1020 ;
      RECT 0.1830 0.0420 0.1950 0.0900 ;
      RECT 0.0710 0.0420 0.0830 0.0900 ;
      RECT 0.3090 0.0300 0.3210 0.0540 ;
    LAYER M2 ;
      RECT 0.3300 0.0900 0.4470 0.1020 ;
      RECT 0.0990 0.0900 0.2790 0.1020 ;
      RECT 0.0150 0.0660 0.3210 0.0780 ;
    LAYER V1 ;
      RECT 0.4350 0.0900 0.4470 0.1020 ;
      RECT 0.3300 0.0900 0.3420 0.1020 ;
      RECT 0.2670 0.0900 0.2790 0.1020 ;
      RECT 0.0990 0.0900 0.1110 0.1020 ;
      RECT 0.3090 0.0660 0.3210 0.0780 ;
      RECT 0.1830 0.0660 0.1950 0.0780 ;
      RECT 0.0710 0.0660 0.0830 0.0780 ;
      RECT 0.0150 0.0660 0.0270 0.0780 ;
  END
END DHLx1

MACRO INVx1
  CLASS CORE ;
  FOREIGN INVx1 ;
  ORIGIN 0 0 ;
  SIZE 0.084 BY 0.144 ;
  SYMMETRY X Y ;
  SITE coreSite ;
  PIN A
    DIRECTION INPUT ;
    USE SIGNAL ;
    PORT
      LAYER M1 ;
        RECT 0.0150 0.0180 0.0270 0.1260 ;
    END
  END A
  PIN Y
    DIRECTION OUTPUT ;
    USE SIGNAL ;
    PORT
      LAYER M1 ;
        RECT 0.0570 0.0180 0.0690 0.1260 ;
    END
  END Y
  PIN VDD
    DIRECTION INOUT ;
    USE POWER ;
    PORT
      LAYER M1 ;
        RECT -0.0090 0.1380 0.0930 0.1500 ;
    END
  END VDD
  PIN VSS
    DIRECTION INOUT ;
    USE GROUND ;
    PORT
      LAYER M1 ;
        RECT -0.0090 -0.0060 0.0930 0.0060 ;
    END
  END VSS
END INVx1

MACRO INVx10
  CLASS CORE ;
  FOREIGN INVx10 ;
  ORIGIN 0 0 ;
  SIZE 0.462 BY 0.144 ;
  SYMMETRY X Y ;
  SITE coreSite ;
  PIN A
    DIRECTION INPUT ;
    USE SIGNAL ;
    PORT
      LAYER M1 ;
        POLYGON 0.0270 0.1260 0.0270 0.0780 0.4050 0.0780 0.4050 0.0660 0.0270 0.0660 0.0270 0.0180 0.0150 0.0180 0.0150 0.1260 ;
    END
  END A
  PIN Y
    DIRECTION OUTPUT ;
    USE SIGNAL ;
    PORT
      LAYER M1 ;
        POLYGON 0.4470 0.1260 0.4470 0.0180 0.0570 0.0180 0.0570 0.0300 0.4350 0.0300 0.4350 0.1140 0.0570 0.1140 0.0570 0.1260 ;
    END
  END Y
  PIN VDD
    DIRECTION INOUT ;
    USE POWER ;
    PORT
      LAYER M1 ;
        RECT -0.0090 0.1380 0.4710 0.1500 ;
    END
  END VDD
  PIN VSS
    DIRECTION INOUT ;
    USE GROUND ;
    PORT
      LAYER M1 ;
        RECT -0.0090 -0.0060 0.4710 0.0060 ;
    END
  END VSS
END INVx10

MACRO INVx12
  CLASS CORE ;
  FOREIGN INVx12 ;
  ORIGIN 0 0 ;
  SIZE 0.546 BY 0.144 ;
  SYMMETRY X Y ;
  SITE coreSite ;
  PIN A
    DIRECTION INPUT ;
    USE SIGNAL ;
    PORT
      LAYER M1 ;
        POLYGON 0.0270 0.1260 0.0270 0.0780 0.4890 0.0780 0.4890 0.0660 0.0270 0.0660 0.0270 0.0180 0.0150 0.0180 0.0150 0.1260 ;
    END
  END A
  PIN Y
    DIRECTION OUTPUT ;
    USE SIGNAL ;
    PORT
      LAYER M1 ;
        POLYGON 0.5310 0.1260 0.5310 0.0180 0.0570 0.0180 0.0570 0.0300 0.5190 0.0300 0.5190 0.1140 0.0570 0.1140 0.0570 0.1260 ;
    END
  END Y
  PIN VDD
    DIRECTION INOUT ;
    USE POWER ;
    PORT
      LAYER M1 ;
        RECT -0.0090 0.1380 0.5550 0.1500 ;
    END
  END VDD
  PIN VSS
    DIRECTION INOUT ;
    USE GROUND ;
    PORT
      LAYER M1 ;
        RECT -0.0090 -0.0060 0.5550 0.0060 ;
    END
  END VSS
END INVx12

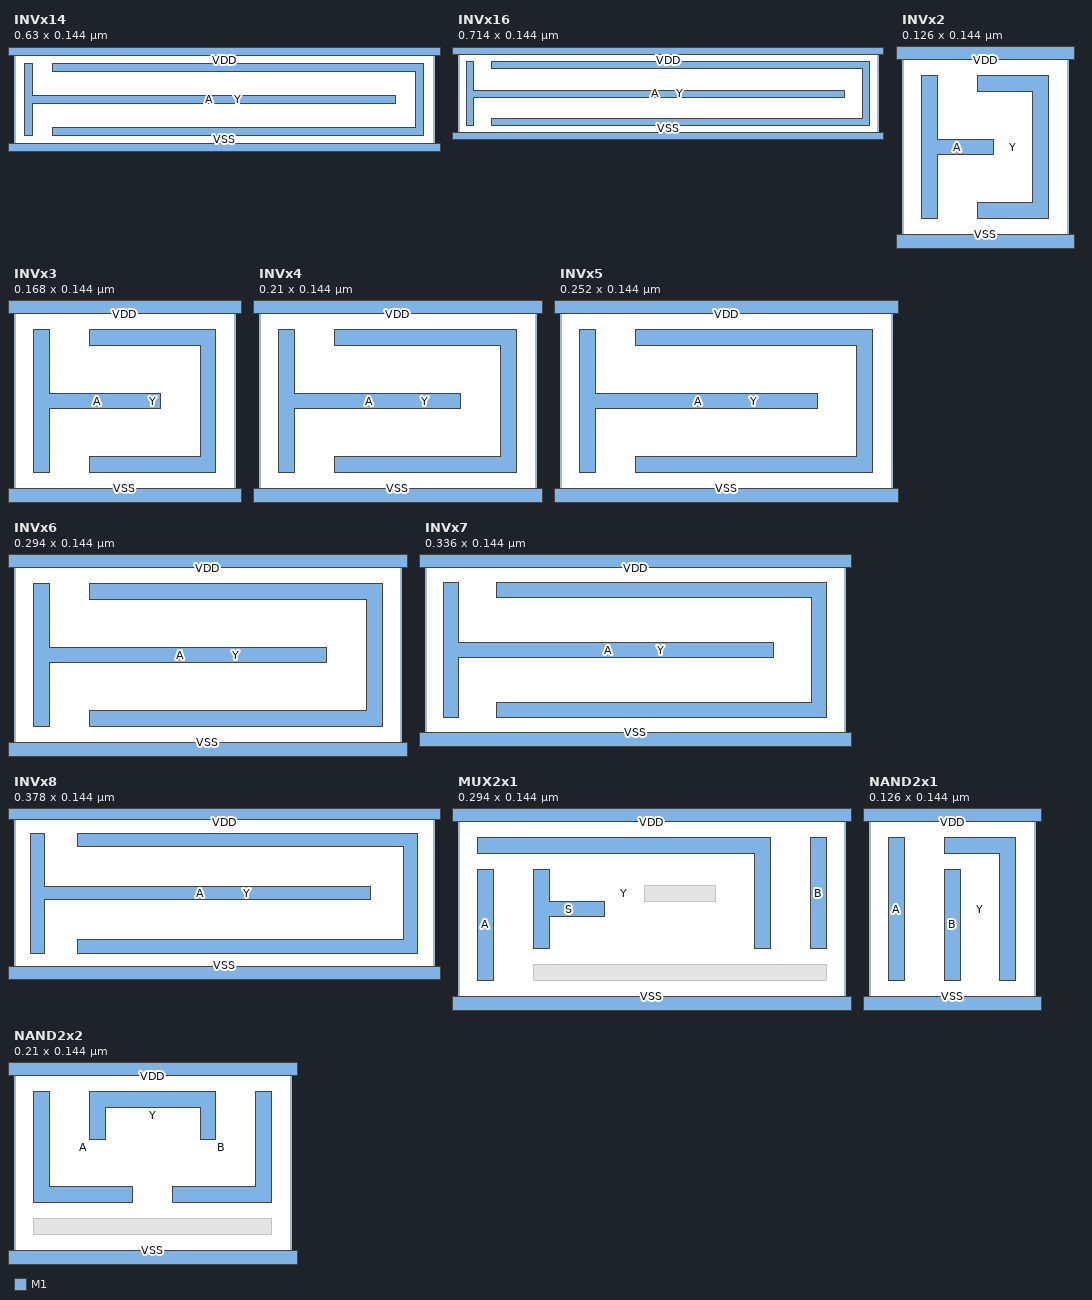
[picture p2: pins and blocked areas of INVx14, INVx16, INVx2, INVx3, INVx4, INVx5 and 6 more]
MACRO INVx14
  CLASS CORE ;
  FOREIGN INVx14 ;
  ORIGIN 0 0 ;
  SIZE 0.63 BY 0.144 ;
  SYMMETRY X Y ;
  SITE coreSite ;
  PIN A
    DIRECTION INPUT ;
    USE SIGNAL ;
    PORT
      LAYER M1 ;
        POLYGON 0.0270 0.1260 0.0270 0.0780 0.5730 0.0780 0.5730 0.0660 0.0270 0.0660 0.0270 0.0180 0.0150 0.0180 0.0150 0.1260 ;
    END
  END A
  PIN Y
    DIRECTION OUTPUT ;
    USE SIGNAL ;
    PORT
      LAYER M1 ;
        POLYGON 0.6150 0.1260 0.6150 0.0180 0.0570 0.0180 0.0570 0.0300 0.6030 0.0300 0.6030 0.1140 0.0570 0.1140 0.0570 0.1260 ;
    END
  END Y
  PIN VDD
    DIRECTION INOUT ;
    USE POWER ;
    PORT
      LAYER M1 ;
        RECT -0.0090 0.1380 0.6390 0.1500 ;
    END
  END VDD
  PIN VSS
    DIRECTION INOUT ;
    USE GROUND ;
    PORT
      LAYER M1 ;
        RECT -0.0090 -0.0060 0.6390 0.0060 ;
    END
  END VSS
END INVx14

MACRO INVx16
  CLASS CORE ;
  FOREIGN INVx16 ;
  ORIGIN 0 0 ;
  SIZE 0.714 BY 0.144 ;
  SYMMETRY X Y ;
  SITE coreSite ;
  PIN A
    DIRECTION INPUT ;
    USE SIGNAL ;
    PORT
      LAYER M1 ;
        POLYGON 0.0270 0.1260 0.0270 0.0780 0.6570 0.0780 0.6570 0.0660 0.0270 0.0660 0.0270 0.0180 0.0150 0.0180 0.0150 0.1260 ;
    END
  END A
  PIN Y
    DIRECTION OUTPUT ;
    USE SIGNAL ;
    PORT
      LAYER M1 ;
        POLYGON 0.6990 0.1260 0.6990 0.0180 0.0570 0.0180 0.0570 0.0300 0.6870 0.0300 0.6870 0.1140 0.0570 0.1140 0.0570 0.1260 ;
    END
  END Y
  PIN VDD
    DIRECTION INOUT ;
    USE POWER ;
    PORT
      LAYER M1 ;
        RECT -0.0090 0.1380 0.7230 0.1500 ;
    END
  END VDD
  PIN VSS
    DIRECTION INOUT ;
    USE GROUND ;
    PORT
      LAYER M1 ;
        RECT -0.0090 -0.0060 0.7230 0.0060 ;
    END
  END VSS
END INVx16

MACRO INVx2
  CLASS CORE ;
  FOREIGN INVx2 ;
  ORIGIN 0 0 ;
  SIZE 0.126 BY 0.144 ;
  SYMMETRY X Y ;
  SITE coreSite ;
  PIN A
    DIRECTION INPUT ;
    USE SIGNAL ;
    PORT
      LAYER M1 ;
        POLYGON 0.0270 0.1260 0.0270 0.0780 0.0690 0.0780 0.0690 0.0660 0.0270 0.0660 0.0270 0.0180 0.0150 0.0180 0.0150 0.1260 ;
    END
  END A
  PIN Y
    DIRECTION OUTPUT ;
    USE SIGNAL ;
    PORT
      LAYER M1 ;
        POLYGON 0.1110 0.1260 0.1110 0.0180 0.0570 0.0180 0.0570 0.0300 0.0990 0.0300 0.0990 0.1140 0.0570 0.1140 0.0570 0.1260 ;
    END
  END Y
  PIN VDD
    DIRECTION INOUT ;
    USE POWER ;
    PORT
      LAYER M1 ;
        RECT -0.0090 0.1380 0.1350 0.1500 ;
    END
  END VDD
  PIN VSS
    DIRECTION INOUT ;
    USE GROUND ;
    PORT
      LAYER M1 ;
        RECT -0.0090 -0.0060 0.1350 0.0060 ;
    END
  END VSS
END INVx2

MACRO INVx3
  CLASS CORE ;
  FOREIGN INVx3 ;
  ORIGIN 0 0 ;
  SIZE 0.168 BY 0.144 ;
  SYMMETRY X Y ;
  SITE coreSite ;
  PIN A
    DIRECTION INPUT ;
    USE SIGNAL ;
    PORT
      LAYER M1 ;
        POLYGON 0.0270 0.1260 0.0270 0.0780 0.1110 0.0780 0.1110 0.0660 0.0270 0.0660 0.0270 0.0180 0.0150 0.0180 0.0150 0.1260 ;
    END
  END A
  PIN Y
    DIRECTION OUTPUT ;
    USE SIGNAL ;
    PORT
      LAYER M1 ;
        POLYGON 0.1530 0.1260 0.1530 0.0180 0.0570 0.0180 0.0570 0.0300 0.1410 0.0300 0.1410 0.1140 0.0570 0.1140 0.0570 0.1260 ;
    END
  END Y
  PIN VDD
    DIRECTION INOUT ;
    USE POWER ;
    PORT
      LAYER M1 ;
        RECT -0.0090 0.1380 0.1770 0.1500 ;
    END
  END VDD
  PIN VSS
    DIRECTION INOUT ;
    USE GROUND ;
    PORT
      LAYER M1 ;
        RECT -0.0090 -0.0060 0.1770 0.0060 ;
    END
  END VSS
END INVx3

MACRO INVx4
  CLASS CORE ;
  FOREIGN INVx4 ;
  ORIGIN 0 0 ;
  SIZE 0.21 BY 0.144 ;
  SYMMETRY X Y ;
  SITE coreSite ;
  PIN A
    DIRECTION INPUT ;
    USE SIGNAL ;
    PORT
      LAYER M1 ;
        POLYGON 0.0270 0.1260 0.0270 0.0780 0.1530 0.0780 0.1530 0.0660 0.0270 0.0660 0.0270 0.0180 0.0150 0.0180 0.0150 0.1260 ;
    END
  END A
  PIN Y
    DIRECTION OUTPUT ;
    USE SIGNAL ;
    PORT
      LAYER M1 ;
        POLYGON 0.1950 0.1260 0.1950 0.0180 0.0570 0.0180 0.0570 0.0300 0.1830 0.0300 0.1830 0.1140 0.0570 0.1140 0.0570 0.1260 ;
    END
  END Y
  PIN VDD
    DIRECTION INOUT ;
    USE POWER ;
    PORT
      LAYER M1 ;
        RECT -0.0090 0.1380 0.2190 0.1500 ;
    END
  END VDD
  PIN VSS
    DIRECTION INOUT ;
    USE GROUND ;
    PORT
      LAYER M1 ;
        RECT -0.0090 -0.0060 0.2190 0.0060 ;
    END
  END VSS
END INVx4

MACRO INVx5
  CLASS CORE ;
  FOREIGN INVx5 ;
  ORIGIN 0 0 ;
  SIZE 0.252 BY 0.144 ;
  SYMMETRY X Y ;
  SITE coreSite ;
  PIN A
    DIRECTION INPUT ;
    USE SIGNAL ;
    PORT
      LAYER M1 ;
        POLYGON 0.0270 0.1260 0.0270 0.0780 0.1950 0.0780 0.1950 0.0660 0.0270 0.0660 0.0270 0.0180 0.0150 0.0180 0.0150 0.1260 ;
    END
  END A
  PIN Y
    DIRECTION OUTPUT ;
    USE SIGNAL ;
    PORT
      LAYER M1 ;
        POLYGON 0.2370 0.1260 0.2370 0.0180 0.0570 0.0180 0.0570 0.0300 0.2250 0.0300 0.2250 0.1140 0.0570 0.1140 0.0570 0.1260 ;
    END
  END Y
  PIN VDD
    DIRECTION INOUT ;
    USE POWER ;
    PORT
      LAYER M1 ;
        RECT -0.0090 0.1380 0.2610 0.1500 ;
    END
  END VDD
  PIN VSS
    DIRECTION INOUT ;
    USE GROUND ;
    PORT
      LAYER M1 ;
        RECT -0.0090 -0.0060 0.2610 0.0060 ;
    END
  END VSS
END INVx5

MACRO INVx6
  CLASS CORE ;
  FOREIGN INVx6 ;
  ORIGIN 0 0 ;
  SIZE 0.294 BY 0.144 ;
  SYMMETRY X Y ;
  SITE coreSite ;
  PIN A
    DIRECTION INPUT ;
    USE SIGNAL ;
    PORT
      LAYER M1 ;
        POLYGON 0.0270 0.1260 0.0270 0.0780 0.2370 0.0780 0.2370 0.0660 0.0270 0.0660 0.0270 0.0180 0.0150 0.0180 0.0150 0.1260 ;
    END
  END A
  PIN Y
    DIRECTION OUTPUT ;
    USE SIGNAL ;
    PORT
      LAYER M1 ;
        POLYGON 0.2790 0.1260 0.2790 0.0180 0.0570 0.0180 0.0570 0.0300 0.2670 0.0300 0.2670 0.1140 0.0570 0.1140 0.0570 0.1260 ;
    END
  END Y
  PIN VDD
    DIRECTION INOUT ;
    USE POWER ;
    PORT
      LAYER M1 ;
        RECT -0.0090 0.1380 0.3030 0.1500 ;
    END
  END VDD
  PIN VSS
    DIRECTION INOUT ;
    USE GROUND ;
    PORT
      LAYER M1 ;
        RECT -0.0090 -0.0060 0.3030 0.0060 ;
    END
  END VSS
END INVx6

MACRO INVx7
  CLASS CORE ;
  FOREIGN INVx7 ;
  ORIGIN 0 0 ;
  SIZE 0.336 BY 0.144 ;
  SYMMETRY X Y ;
  SITE coreSite ;
  PIN A
    DIRECTION INPUT ;
    USE SIGNAL ;
    PORT
      LAYER M1 ;
        POLYGON 0.0270 0.1260 0.0270 0.0780 0.2790 0.0780 0.2790 0.0660 0.0270 0.0660 0.0270 0.0180 0.0150 0.0180 0.0150 0.1260 ;
    END
  END A
  PIN Y
    DIRECTION OUTPUT ;
    USE SIGNAL ;
    PORT
      LAYER M1 ;
        POLYGON 0.3210 0.1260 0.3210 0.0180 0.0570 0.0180 0.0570 0.0300 0.3090 0.0300 0.3090 0.1140 0.0570 0.1140 0.0570 0.1260 ;
    END
  END Y
  PIN VDD
    DIRECTION INOUT ;
    USE POWER ;
    PORT
      LAYER M1 ;
        RECT -0.0090 0.1380 0.3450 0.1500 ;
    END
  END VDD
  PIN VSS
    DIRECTION INOUT ;
    USE GROUND ;
    PORT
      LAYER M1 ;
        RECT -0.0090 -0.0060 0.3450 0.0060 ;
    END
  END VSS
END INVx7

MACRO INVx8
  CLASS CORE ;
  FOREIGN INVx8 ;
  ORIGIN 0 0 ;
  SIZE 0.378 BY 0.144 ;
  SYMMETRY X Y ;
  SITE coreSite ;
  PIN A
    DIRECTION INPUT ;
    USE SIGNAL ;
    PORT
      LAYER M1 ;
        POLYGON 0.0270 0.1260 0.0270 0.0780 0.3210 0.0780 0.3210 0.0660 0.0270 0.0660 0.0270 0.0180 0.0150 0.0180 0.0150 0.1260 ;
    END
  END A
  PIN Y
    DIRECTION OUTPUT ;
    USE SIGNAL ;
    PORT
      LAYER M1 ;
        POLYGON 0.3630 0.1260 0.3630 0.0180 0.0570 0.0180 0.0570 0.0300 0.3510 0.0300 0.3510 0.1140 0.0570 0.1140 0.0570 0.1260 ;
    END
  END Y
  PIN VDD
    DIRECTION INOUT ;
    USE POWER ;
    PORT
      LAYER M1 ;
        RECT -0.0090 0.1380 0.3870 0.1500 ;
    END
  END VDD
  PIN VSS
    DIRECTION INOUT ;
    USE GROUND ;
    PORT
      LAYER M1 ;
        RECT -0.0090 -0.0060 0.3870 0.0060 ;
    END
  END VSS
END INVx8

MACRO MUX2x1
  CLASS CORE ;
  FOREIGN MUX2x1 ;
  ORIGIN 0 0 ;
  SIZE 0.294 BY 0.144 ;
  SYMMETRY X Y ;
  SITE coreSite ;
  PIN A
    DIRECTION INPUT ;
    USE SIGNAL ;
    PORT
      LAYER M1 ;
        RECT 0.0150 0.0180 0.0270 0.1020 ;
    END
  END A
  PIN B
    DIRECTION INPUT ;
    USE SIGNAL ;
    PORT
      LAYER M1 ;
        RECT 0.2670 0.0420 0.2790 0.1260 ;
    END
  END B
  PIN S
    DIRECTION INPUT ;
    USE SIGNAL ;
    PORT
      LAYER M1 ;
        POLYGON 0.0690 0.1020 0.0690 0.0780 0.1110 0.0780 0.1110 0.0660 0.0690 0.0660 0.0690 0.0420 0.0570 0.0420 0.0570 0.1020 ;
    END
  END S
  PIN Y
    DIRECTION OUTPUT ;
    USE SIGNAL ;
    PORT
      LAYER M1 ;
        POLYGON 0.2370 0.1260 0.2370 0.0420 0.2250 0.0420 0.2250 0.1140 0.0150 0.1140 0.0150 0.1260 ;
    END
  END Y
  PIN VDD
    DIRECTION INOUT ;
    USE POWER ;
    PORT
      LAYER M1 ;
        RECT -0.0090 0.1380 0.3030 0.1500 ;
    END
  END VDD
  PIN VSS
    DIRECTION INOUT ;
    USE GROUND ;
    PORT
      LAYER M1 ;
        RECT -0.0090 -0.0060 0.3030 0.0060 ;
    END
  END VSS
  OBS
    LAYER M1 ;
      RECT 0.1410 0.0780 0.1950 0.0900 ;
      RECT 0.0570 0.0180 0.2790 0.0300 ;
  END
END MUX2x1

MACRO NAND2x1
  CLASS CORE ;
  FOREIGN NAND2x1 ;
  ORIGIN 0 0 ;
  SIZE 0.126 BY 0.144 ;
  SYMMETRY X Y ;
  SITE coreSite ;
  PIN A
    DIRECTION INPUT ;
    USE SIGNAL ;
    PORT
      LAYER M1 ;
        RECT 0.0150 0.0180 0.0270 0.1260 ;
    END
  END A
  PIN B
    DIRECTION INPUT ;
    USE SIGNAL ;
    PORT
      LAYER M1 ;
        RECT 0.0570 0.0180 0.0690 0.1020 ;
    END
  END B
  PIN Y
    DIRECTION OUTPUT ;
    USE SIGNAL ;
    PORT
      LAYER M1 ;
        POLYGON 0.1110 0.1260 0.1110 0.0180 0.0990 0.0180 0.0990 0.1140 0.0570 0.1140 0.0570 0.1260 ;
    END
  END Y
  PIN VDD
    DIRECTION INOUT ;
    USE POWER ;
    PORT
      LAYER M1 ;
        RECT -0.0090 0.1380 0.1350 0.1500 ;
    END
  END VDD
  PIN VSS
    DIRECTION INOUT ;
    USE GROUND ;
    PORT
      LAYER M1 ;
        RECT -0.0090 -0.0060 0.1350 0.0060 ;
    END
  END VSS
END NAND2x1

MACRO NAND2x2
  CLASS CORE ;
  FOREIGN NAND2x2 ;
  ORIGIN 0 0 ;
  SIZE 0.21 BY 0.144 ;
  SYMMETRY X Y ;
  SITE coreSite ;
  PIN A
    DIRECTION INPUT ;
    USE SIGNAL ;
    PORT
      LAYER M1 ;
        POLYGON 0.0270 0.1260 0.0270 0.0540 0.0900 0.0540 0.0900 0.0420 0.0150 0.0420 0.0150 0.1260 ;
    END
  END A
  PIN B
    DIRECTION INPUT ;
    USE SIGNAL ;
    PORT
      LAYER M1 ;
        POLYGON 0.1950 0.1260 0.1950 0.0420 0.1200 0.0420 0.1200 0.0540 0.1830 0.0540 0.1830 0.1260 ;
    END
  END B
  PIN Y
    DIRECTION OUTPUT ;
    USE SIGNAL ;
    PORT
      LAYER M1 ;
        POLYGON 0.1530 0.1260 0.1530 0.0900 0.1410 0.0900 0.1410 0.1140 0.0690 0.1140 0.0690 0.0900 0.0570 0.0900 0.0570 0.1260 ;
    END
  END Y
  PIN VDD
    DIRECTION INOUT ;
    USE POWER ;
    PORT
      LAYER M1 ;
        RECT -0.0090 0.1380 0.2190 0.1500 ;
    END
  END VDD
  PIN VSS
    DIRECTION INOUT ;
    USE GROUND ;
    PORT
      LAYER M1 ;
        RECT -0.0090 -0.0060 0.2190 0.0060 ;
    END
  END VSS
  OBS
    LAYER M1 ;
      RECT 0.0150 0.0180 0.1950 0.0300 ;
  END
END NAND2x2

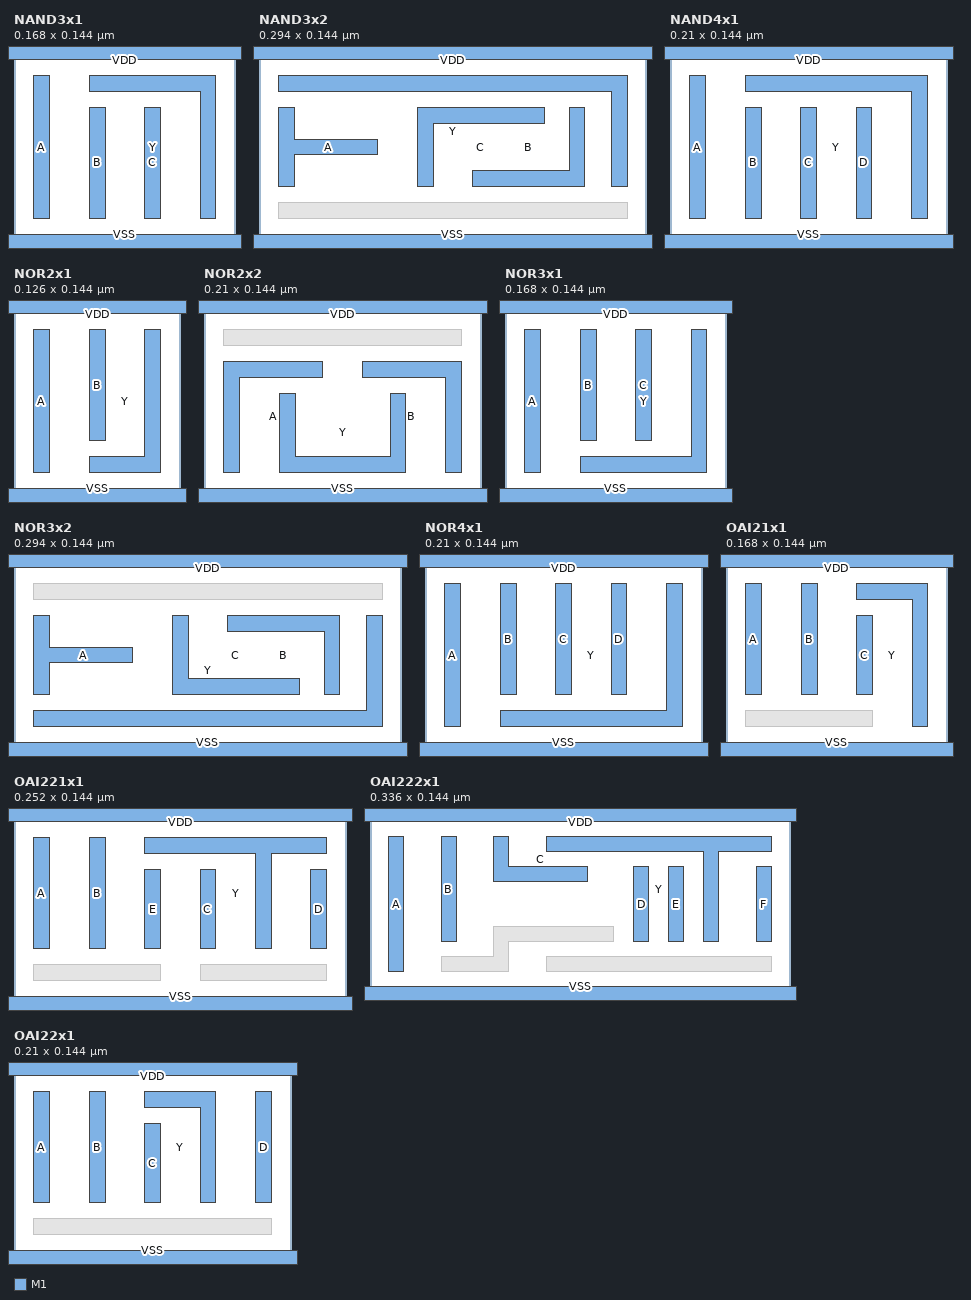
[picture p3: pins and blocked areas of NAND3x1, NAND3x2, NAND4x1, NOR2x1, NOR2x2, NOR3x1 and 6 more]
MACRO NAND3x1
  CLASS CORE ;
  FOREIGN NAND3x1 ;
  ORIGIN 0 0 ;
  SIZE 0.168 BY 0.144 ;
  SYMMETRY X Y ;
  SITE coreSite ;
  PIN A
    DIRECTION INPUT ;
    USE SIGNAL ;
    PORT
      LAYER M1 ;
        RECT 0.0150 0.0180 0.0270 0.1260 ;
    END
  END A
  PIN B
    DIRECTION INPUT ;
    USE SIGNAL ;
    PORT
      LAYER M1 ;
        RECT 0.0570 0.0180 0.0690 0.1020 ;
    END
  END B
  PIN C
    DIRECTION INPUT ;
    USE SIGNAL ;
    PORT
      LAYER M1 ;
        RECT 0.0990 0.0180 0.1110 0.1020 ;
    END
  END C
  PIN Y
    DIRECTION OUTPUT ;
    USE SIGNAL ;
    PORT
      LAYER M1 ;
        POLYGON 0.1530 0.1260 0.1530 0.0180 0.1410 0.0180 0.1410 0.1140 0.0570 0.1140 0.0570 0.1260 ;
    END
  END Y
  PIN VDD
    DIRECTION INOUT ;
    USE POWER ;
    PORT
      LAYER M1 ;
        RECT -0.0090 0.1380 0.1770 0.1500 ;
    END
  END VDD
  PIN VSS
    DIRECTION INOUT ;
    USE GROUND ;
    PORT
      LAYER M1 ;
        RECT -0.0090 -0.0060 0.1770 0.0060 ;
    END
  END VSS
END NAND3x1

MACRO NAND3x2
  CLASS CORE ;
  FOREIGN NAND3x2 ;
  ORIGIN 0 0 ;
  SIZE 0.294 BY 0.144 ;
  SYMMETRY X Y ;
  SITE coreSite ;
  PIN A
    DIRECTION INPUT ;
    USE SIGNAL ;
    PORT
      LAYER M1 ;
        POLYGON 0.0270 0.1020 0.0270 0.0780 0.0900 0.0780 0.0900 0.0660 0.0270 0.0660 0.0270 0.0420 0.0150 0.0420 0.0150 0.1020 ;
    END
  END A
  PIN B
    DIRECTION INPUT ;
    USE SIGNAL ;
    PORT
      LAYER M1 ;
        POLYGON 0.2470 0.1020 0.2470 0.0420 0.1620 0.0420 0.1620 0.0540 0.2350 0.0540 0.2350 0.1020 ;
    END
  END B
  PIN C
    DIRECTION INPUT ;
    USE SIGNAL ;
    PORT
      LAYER M1 ;
        POLYGON 0.2160 0.1020 0.2160 0.0900 0.1320 0.0900 0.1320 0.0420 0.1200 0.0420 0.1200 0.1020 ;
    END
  END C
  PIN Y
    DIRECTION OUTPUT ;
    USE SIGNAL ;
    PORT
      LAYER M1 ;
        POLYGON 0.2790 0.1260 0.2790 0.0420 0.2670 0.0420 0.2670 0.1140 0.0150 0.1140 0.0150 0.1260 ;
    END
  END Y
  PIN VDD
    DIRECTION INOUT ;
    USE POWER ;
    PORT
      LAYER M1 ;
        RECT -0.0090 0.1380 0.3030 0.1500 ;
    END
  END VDD
  PIN VSS
    DIRECTION INOUT ;
    USE GROUND ;
    PORT
      LAYER M1 ;
        RECT -0.0090 -0.0060 0.3030 0.0060 ;
    END
  END VSS
  OBS
    LAYER M1 ;
      RECT 0.0150 0.0180 0.2790 0.0300 ;
  END
END NAND3x2

MACRO NAND4x1
  CLASS CORE ;
  FOREIGN NAND4x1 ;
  ORIGIN 0 0 ;
  SIZE 0.21 BY 0.144 ;
  SYMMETRY X Y ;
  SITE coreSite ;
  PIN A
    DIRECTION INPUT ;
    USE SIGNAL ;
    PORT
      LAYER M1 ;
        RECT 0.0150 0.0180 0.0270 0.1260 ;
    END
  END A
  PIN B
    DIRECTION INPUT ;
    USE SIGNAL ;
    PORT
      LAYER M1 ;
        RECT 0.0570 0.0180 0.0690 0.1020 ;
    END
  END B
  PIN C
    DIRECTION INPUT ;
    USE SIGNAL ;
    PORT
      LAYER M1 ;
        RECT 0.0990 0.0180 0.1110 0.1020 ;
    END
  END C
  PIN D
    DIRECTION INPUT ;
    USE SIGNAL ;
    PORT
      LAYER M1 ;
        RECT 0.1410 0.0180 0.1530 0.1020 ;
    END
  END D
  PIN Y
    DIRECTION OUTPUT ;
    USE SIGNAL ;
    PORT
      LAYER M1 ;
        POLYGON 0.1950 0.1260 0.1950 0.0180 0.1830 0.0180 0.1830 0.1140 0.0570 0.1140 0.0570 0.1260 ;
    END
  END Y
  PIN VDD
    DIRECTION INOUT ;
    USE POWER ;
    PORT
      LAYER M1 ;
        RECT -0.0090 0.1380 0.2190 0.1500 ;
    END
  END VDD
  PIN VSS
    DIRECTION INOUT ;
    USE GROUND ;
    PORT
      LAYER M1 ;
        RECT -0.0090 -0.0060 0.2190 0.0060 ;
    END
  END VSS
END NAND4x1

MACRO NOR2x1
  CLASS CORE ;
  FOREIGN NOR2x1 ;
  ORIGIN 0 0 ;
  SIZE 0.126 BY 0.144 ;
  SYMMETRY X Y ;
  SITE coreSite ;
  PIN A
    DIRECTION INPUT ;
    USE SIGNAL ;
    PORT
      LAYER M1 ;
        RECT 0.0150 0.0180 0.0270 0.1260 ;
    END
  END A
  PIN B
    DIRECTION INPUT ;
    USE SIGNAL ;
    PORT
      LAYER M1 ;
        RECT 0.0570 0.0420 0.0690 0.1260 ;
    END
  END B
  PIN Y
    DIRECTION OUTPUT ;
    USE SIGNAL ;
    PORT
      LAYER M1 ;
        POLYGON 0.1110 0.1260 0.1110 0.0180 0.0570 0.0180 0.0570 0.0300 0.0990 0.0300 0.0990 0.1260 ;
    END
  END Y
  PIN VDD
    DIRECTION INOUT ;
    USE POWER ;
    PORT
      LAYER M1 ;
        RECT -0.0090 0.1380 0.1350 0.1500 ;
    END
  END VDD
  PIN VSS
    DIRECTION INOUT ;
    USE GROUND ;
    PORT
      LAYER M1 ;
        RECT -0.0090 -0.0060 0.1350 0.0060 ;
    END
  END VSS
END NOR2x1

MACRO NOR2x2
  CLASS CORE ;
  FOREIGN NOR2x2 ;
  ORIGIN 0 0 ;
  SIZE 0.21 BY 0.144 ;
  SYMMETRY X Y ;
  SITE coreSite ;
  PIN A
    DIRECTION INPUT ;
    USE SIGNAL ;
    PORT
      LAYER M1 ;
        POLYGON 0.0900 0.1020 0.0900 0.0900 0.0270 0.0900 0.0270 0.0180 0.0150 0.0180 0.0150 0.1020 ;
    END
  END A
  PIN B
    DIRECTION INPUT ;
    USE SIGNAL ;
    PORT
      LAYER M1 ;
        POLYGON 0.1950 0.1020 0.1950 0.0180 0.1830 0.0180 0.1830 0.0900 0.1200 0.0900 0.1200 0.1020 ;
    END
  END B
  PIN Y
    DIRECTION OUTPUT ;
    USE SIGNAL ;
    PORT
      LAYER M1 ;
        POLYGON 0.1530 0.0780 0.1530 0.0180 0.0570 0.0180 0.0570 0.0780 0.0690 0.0780 0.0690 0.0300 0.1410 0.0300 0.1410 0.0780 ;
    END
  END Y
  PIN VDD
    DIRECTION INOUT ;
    USE POWER ;
    PORT
      LAYER M1 ;
        RECT -0.0090 0.1380 0.2190 0.1500 ;
    END
  END VDD
  PIN VSS
    DIRECTION INOUT ;
    USE GROUND ;
    PORT
      LAYER M1 ;
        RECT -0.0090 -0.0060 0.2190 0.0060 ;
    END
  END VSS
  OBS
    LAYER M1 ;
      RECT 0.0150 0.1140 0.1950 0.1260 ;
  END
END NOR2x2

MACRO NOR3x1
  CLASS CORE ;
  FOREIGN NOR3x1 ;
  ORIGIN 0 0 ;
  SIZE 0.168 BY 0.144 ;
  SYMMETRY X Y ;
  SITE coreSite ;
  PIN A
    DIRECTION INPUT ;
    USE SIGNAL ;
    PORT
      LAYER M1 ;
        RECT 0.0150 0.0180 0.0270 0.1260 ;
    END
  END A
  PIN B
    DIRECTION INPUT ;
    USE SIGNAL ;
    PORT
      LAYER M1 ;
        RECT 0.0570 0.0420 0.0690 0.1260 ;
    END
  END B
  PIN C
    DIRECTION INPUT ;
    USE SIGNAL ;
    PORT
      LAYER M1 ;
        RECT 0.0990 0.0420 0.1110 0.1260 ;
    END
  END C
  PIN Y
    DIRECTION OUTPUT ;
    USE SIGNAL ;
    PORT
      LAYER M1 ;
        POLYGON 0.1530 0.1260 0.1530 0.0180 0.0570 0.0180 0.0570 0.0300 0.1410 0.0300 0.1410 0.1260 ;
    END
  END Y
  PIN VDD
    DIRECTION INOUT ;
    USE POWER ;
    PORT
      LAYER M1 ;
        RECT -0.0090 0.1380 0.1770 0.1500 ;
    END
  END VDD
  PIN VSS
    DIRECTION INOUT ;
    USE GROUND ;
    PORT
      LAYER M1 ;
        RECT -0.0090 -0.0060 0.1770 0.0060 ;
    END
  END VSS
END NOR3x1

MACRO NOR3x2
  CLASS CORE ;
  FOREIGN NOR3x2 ;
  ORIGIN 0 0 ;
  SIZE 0.294 BY 0.144 ;
  SYMMETRY X Y ;
  SITE coreSite ;
  PIN A
    DIRECTION INPUT ;
    USE SIGNAL ;
    PORT
      LAYER M1 ;
        POLYGON 0.0270 0.1020 0.0270 0.0780 0.0900 0.0780 0.0900 0.0660 0.0270 0.0660 0.0270 0.0420 0.0150 0.0420 0.0150 0.1020 ;
    END
  END A
  PIN B
    DIRECTION INPUT ;
    USE SIGNAL ;
    PORT
      LAYER M1 ;
        POLYGON 0.2470 0.1020 0.2470 0.0420 0.2350 0.0420 0.2350 0.0900 0.1620 0.0900 0.1620 0.1020 ;
    END
  END B
  PIN C
    DIRECTION INPUT ;
    USE SIGNAL ;
    PORT
      LAYER M1 ;
        POLYGON 0.1320 0.1020 0.1320 0.0540 0.2160 0.0540 0.2160 0.0420 0.1200 0.0420 0.1200 0.1020 ;
    END
  END C
  PIN Y
    DIRECTION OUTPUT ;
    USE SIGNAL ;
    PORT
      LAYER M1 ;
        POLYGON 0.2790 0.1020 0.2790 0.0180 0.0150 0.0180 0.0150 0.0300 0.2670 0.0300 0.2670 0.1020 ;
    END
  END Y
  PIN VDD
    DIRECTION INOUT ;
    USE POWER ;
    PORT
      LAYER M1 ;
        RECT -0.0090 0.1380 0.3030 0.1500 ;
    END
  END VDD
  PIN VSS
    DIRECTION INOUT ;
    USE GROUND ;
    PORT
      LAYER M1 ;
        RECT -0.0090 -0.0060 0.3030 0.0060 ;
    END
  END VSS
  OBS
    LAYER M1 ;
      RECT 0.0150 0.1140 0.2790 0.1260 ;
  END
END NOR3x2

MACRO NOR4x1
  CLASS CORE ;
  FOREIGN NOR4x1 ;
  ORIGIN 0 0 ;
  SIZE 0.21 BY 0.144 ;
  SYMMETRY X Y ;
  SITE coreSite ;
  PIN A
    DIRECTION INPUT ;
    USE SIGNAL ;
    PORT
      LAYER M1 ;
        RECT 0.0150 0.0180 0.0270 0.1260 ;
    END
  END A
  PIN B
    DIRECTION INPUT ;
    USE SIGNAL ;
    PORT
      LAYER M1 ;
        RECT 0.0570 0.0420 0.0690 0.1260 ;
    END
  END B
  PIN C
    DIRECTION INPUT ;
    USE SIGNAL ;
    PORT
      LAYER M1 ;
        RECT 0.0990 0.0420 0.1110 0.1260 ;
    END
  END C
  PIN D
    DIRECTION INPUT ;
    USE SIGNAL ;
    PORT
      LAYER M1 ;
        RECT 0.1410 0.0420 0.1530 0.1260 ;
    END
  END D
  PIN Y
    DIRECTION OUTPUT ;
    USE SIGNAL ;
    PORT
      LAYER M1 ;
        POLYGON 0.1950 0.1260 0.1950 0.0180 0.0570 0.0180 0.0570 0.0300 0.1830 0.0300 0.1830 0.1260 ;
    END
  END Y
  PIN VDD
    DIRECTION INOUT ;
    USE POWER ;
    PORT
      LAYER M1 ;
        RECT -0.0090 0.1380 0.2190 0.1500 ;
    END
  END VDD
  PIN VSS
    DIRECTION INOUT ;
    USE GROUND ;
    PORT
      LAYER M1 ;
        RECT -0.0090 -0.0060 0.2190 0.0060 ;
    END
  END VSS
END NOR4x1

MACRO OAI21x1
  CLASS CORE ;
  FOREIGN OAI21x1 ;
  ORIGIN 0 0 ;
  SIZE 0.168 BY 0.144 ;
  SYMMETRY X Y ;
  SITE coreSite ;
  PIN A
    DIRECTION INPUT ;
    USE SIGNAL ;
    PORT
      LAYER M1 ;
        RECT 0.0150 0.0420 0.0270 0.1260 ;
    END
  END A
  PIN B
    DIRECTION INPUT ;
    USE SIGNAL ;
    PORT
      LAYER M1 ;
        RECT 0.0570 0.0420 0.0690 0.1260 ;
    END
  END B
  PIN C
    DIRECTION INPUT ;
    USE SIGNAL ;
    PORT
      LAYER M1 ;
        RECT 0.0990 0.0420 0.1110 0.1020 ;
    END
  END C
  PIN Y
    DIRECTION OUTPUT ;
    USE SIGNAL ;
    PORT
      LAYER M1 ;
        POLYGON 0.1530 0.1260 0.1530 0.0180 0.1410 0.0180 0.1410 0.1140 0.0990 0.1140 0.0990 0.1260 ;
    END
  END Y
  PIN VDD
    DIRECTION INOUT ;
    USE POWER ;
    PORT
      LAYER M1 ;
        RECT -0.0090 0.1380 0.1770 0.1500 ;
    END
  END VDD
  PIN VSS
    DIRECTION INOUT ;
    USE GROUND ;
    PORT
      LAYER M1 ;
        RECT -0.0090 -0.0060 0.1770 0.0060 ;
    END
  END VSS
  OBS
    LAYER M1 ;
      RECT 0.0150 0.0180 0.1110 0.0300 ;
  END
END OAI21x1

MACRO OAI221x1
  CLASS CORE ;
  FOREIGN OAI221x1 ;
  ORIGIN 0 0 ;
  SIZE 0.252 BY 0.144 ;
  SYMMETRY X Y ;
  SITE coreSite ;
  PIN A
    DIRECTION INPUT ;
    USE SIGNAL ;
    PORT
      LAYER M1 ;
        RECT 0.0150 0.0420 0.0270 0.1260 ;
    END
  END A
  PIN B
    DIRECTION INPUT ;
    USE SIGNAL ;
    PORT
      LAYER M1 ;
        RECT 0.0570 0.0420 0.0690 0.1260 ;
    END
  END B
  PIN C
    DIRECTION INPUT ;
    USE SIGNAL ;
    PORT
      LAYER M1 ;
        RECT 0.1410 0.0420 0.1530 0.1020 ;
    END
  END C
  PIN D
    DIRECTION INPUT ;
    USE SIGNAL ;
    PORT
      LAYER M1 ;
        RECT 0.2250 0.0420 0.2370 0.1020 ;
    END
  END D
  PIN E
    DIRECTION INPUT ;
    USE SIGNAL ;
    PORT
      LAYER M1 ;
        RECT 0.0990 0.0420 0.1110 0.1020 ;
    END
  END E
  PIN Y
    DIRECTION OUTPUT ;
    USE SIGNAL ;
    PORT
      LAYER M1 ;
        POLYGON 0.2370 0.1260 0.2370 0.1140 0.1950 0.1140 0.1950 0.0420 0.1830 0.0420 0.1830 0.1140 0.0990 0.1140 0.0990 0.1260 ;
    END
  END Y
  PIN VDD
    DIRECTION INOUT ;
    USE POWER ;
    PORT
      LAYER M1 ;
        RECT -0.0090 0.1380 0.2610 0.1500 ;
    END
  END VDD
  PIN VSS
    DIRECTION INOUT ;
    USE GROUND ;
    PORT
      LAYER M1 ;
        RECT -0.0090 -0.0060 0.2610 0.0060 ;
    END
  END VSS
  OBS
    LAYER M1 ;
      RECT 0.1410 0.0180 0.2370 0.0300 ;
      RECT 0.0150 0.0180 0.1110 0.0300 ;
  END
END OAI221x1

MACRO OAI222x1
  CLASS CORE ;
  FOREIGN OAI222x1 ;
  ORIGIN 0 0 ;
  SIZE 0.336 BY 0.144 ;
  SYMMETRY X Y ;
  SITE coreSite ;
  PIN A
    DIRECTION INPUT ;
    USE SIGNAL ;
    PORT
      LAYER M1 ;
        RECT 0.0150 0.0180 0.0270 0.1260 ;
    END
  END A
  PIN B
    DIRECTION INPUT ;
    USE SIGNAL ;
    PORT
      LAYER M1 ;
        RECT 0.0570 0.0420 0.0690 0.1260 ;
    END
  END B
  PIN C
    DIRECTION INPUT ;
    USE SIGNAL ;
    PORT
      LAYER M1 ;
        POLYGON 0.1110 0.1260 0.1110 0.1020 0.1740 0.1020 0.1740 0.0900 0.0990 0.0900 0.0990 0.1260 ;
    END
  END C
  PIN D
    DIRECTION INPUT ;
    USE SIGNAL ;
    PORT
      LAYER M1 ;
        RECT 0.2110 0.0420 0.2230 0.1020 ;
    END
  END D
  PIN E
    DIRECTION INPUT ;
    USE SIGNAL ;
    PORT
      LAYER M1 ;
        RECT 0.2390 0.0420 0.2510 0.1020 ;
    END
  END E
  PIN F
    DIRECTION INPUT ;
    USE SIGNAL ;
    PORT
      LAYER M1 ;
        RECT 0.3090 0.0420 0.3210 0.1020 ;
    END
  END F
  PIN Y
    DIRECTION OUTPUT ;
    USE SIGNAL ;
    PORT
      LAYER M1 ;
        POLYGON 0.3210 0.1260 0.3210 0.1140 0.2790 0.1140 0.2790 0.0420 0.2670 0.0420 0.2670 0.1140 0.1410 0.1140 0.1410 0.1260 ;
    END
  END Y
  PIN VDD
    DIRECTION INOUT ;
    USE POWER ;
    PORT
      LAYER M1 ;
        RECT -0.0090 0.1380 0.3450 0.1500 ;
    END
  END VDD
  PIN VSS
    DIRECTION INOUT ;
    USE GROUND ;
    PORT
      LAYER M1 ;
        RECT -0.0090 -0.0060 0.3450 0.0060 ;
    END
  END VSS
  OBS
    LAYER M1 ;
      POLYGON 0.1950 0.0540 0.1950 0.0420 0.1110 0.0420 0.1110 0.0180 0.0570 0.0180 0.0570 0.0300 0.0990 0.0300 0.0990 0.0540 ;
      RECT 0.1410 0.0180 0.3210 0.0300 ;
  END
END OAI222x1

MACRO OAI22x1
  CLASS CORE ;
  FOREIGN OAI22x1 ;
  ORIGIN 0 0 ;
  SIZE 0.21 BY 0.144 ;
  SYMMETRY X Y ;
  SITE coreSite ;
  PIN A
    DIRECTION INPUT ;
    USE SIGNAL ;
    PORT
      LAYER M1 ;
        RECT 0.0150 0.0420 0.0270 0.1260 ;
    END
  END A
  PIN B
    DIRECTION INPUT ;
    USE SIGNAL ;
    PORT
      LAYER M1 ;
        RECT 0.0570 0.0420 0.0690 0.1260 ;
    END
  END B
  PIN C
    DIRECTION INPUT ;
    USE SIGNAL ;
    PORT
      LAYER M1 ;
        RECT 0.0990 0.0420 0.1110 0.1020 ;
    END
  END C
  PIN D
    DIRECTION INPUT ;
    USE SIGNAL ;
    PORT
      LAYER M1 ;
        RECT 0.1830 0.0420 0.1950 0.1260 ;
    END
  END D
  PIN Y
    DIRECTION OUTPUT ;
    USE SIGNAL ;
    PORT
      LAYER M1 ;
        POLYGON 0.1530 0.1260 0.1530 0.0420 0.1410 0.0420 0.1410 0.1140 0.0990 0.1140 0.0990 0.1260 ;
    END
  END Y
  PIN VDD
    DIRECTION INOUT ;
    USE POWER ;
    PORT
      LAYER M1 ;
        RECT -0.0090 0.1380 0.2190 0.1500 ;
    END
  END VDD
  PIN VSS
    DIRECTION INOUT ;
    USE GROUND ;
    PORT
      LAYER M1 ;
        RECT -0.0090 -0.0060 0.2190 0.0060 ;
    END
  END VSS
  OBS
    LAYER M1 ;
      RECT 0.0150 0.0180 0.1950 0.0300 ;
  END
END OAI22x1

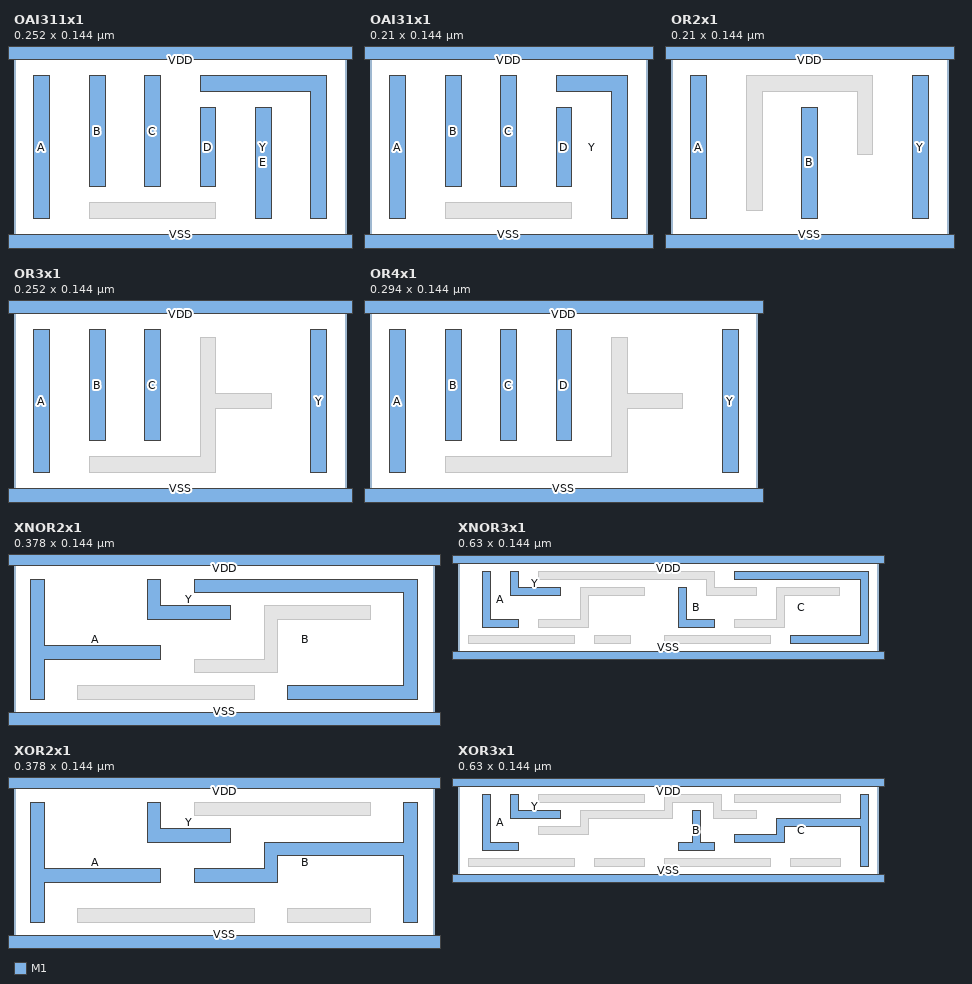
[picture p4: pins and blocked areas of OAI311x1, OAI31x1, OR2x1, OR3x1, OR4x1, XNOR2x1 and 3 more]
MACRO OAI311x1
  CLASS CORE ;
  FOREIGN OAI311x1 ;
  ORIGIN 0 0 ;
  SIZE 0.252 BY 0.144 ;
  SYMMETRY X Y ;
  SITE coreSite ;
  PIN A
    DIRECTION INPUT ;
    USE SIGNAL ;
    PORT
      LAYER M1 ;
        RECT 0.0150 0.0180 0.0270 0.1260 ;
    END
  END A
  PIN B
    DIRECTION INPUT ;
    USE SIGNAL ;
    PORT
      LAYER M1 ;
        RECT 0.0570 0.0420 0.0690 0.1260 ;
    END
  END B
  PIN C
    DIRECTION INPUT ;
    USE SIGNAL ;
    PORT
      LAYER M1 ;
        RECT 0.0990 0.0420 0.1110 0.1260 ;
    END
  END C
  PIN D
    DIRECTION INPUT ;
    USE SIGNAL ;
    PORT
      LAYER M1 ;
        RECT 0.1410 0.0420 0.1530 0.1020 ;
    END
  END D
  PIN E
    DIRECTION INPUT ;
    USE SIGNAL ;
    PORT
      LAYER M1 ;
        RECT 0.1830 0.0180 0.1950 0.1020 ;
    END
  END E
  PIN Y
    DIRECTION OUTPUT ;
    USE SIGNAL ;
    PORT
      LAYER M1 ;
        POLYGON 0.2370 0.1260 0.2370 0.0180 0.2250 0.0180 0.2250 0.1140 0.1410 0.1140 0.1410 0.1260 ;
    END
  END Y
  PIN VDD
    DIRECTION INOUT ;
    USE POWER ;
    PORT
      LAYER M1 ;
        RECT -0.0090 0.1380 0.2610 0.1500 ;
    END
  END VDD
  PIN VSS
    DIRECTION INOUT ;
    USE GROUND ;
    PORT
      LAYER M1 ;
        RECT -0.0090 -0.0060 0.2610 0.0060 ;
    END
  END VSS
  OBS
    LAYER M1 ;
      RECT 0.0570 0.0180 0.1530 0.0300 ;
  END
END OAI311x1

MACRO OAI31x1
  CLASS CORE ;
  FOREIGN OAI31x1 ;
  ORIGIN 0 0 ;
  SIZE 0.21 BY 0.144 ;
  SYMMETRY X Y ;
  SITE coreSite ;
  PIN A
    DIRECTION INPUT ;
    USE SIGNAL ;
    PORT
      LAYER M1 ;
        RECT 0.0150 0.0180 0.0270 0.1260 ;
    END
  END A
  PIN B
    DIRECTION INPUT ;
    USE SIGNAL ;
    PORT
      LAYER M1 ;
        RECT 0.0570 0.0420 0.0690 0.1260 ;
    END
  END B
  PIN C
    DIRECTION INPUT ;
    USE SIGNAL ;
    PORT
      LAYER M1 ;
        RECT 0.0990 0.0420 0.1110 0.1260 ;
    END
  END C
  PIN D
    DIRECTION INPUT ;
    USE SIGNAL ;
    PORT
      LAYER M1 ;
        RECT 0.1410 0.0420 0.1530 0.1020 ;
    END
  END D
  PIN Y
    DIRECTION OUTPUT ;
    USE SIGNAL ;
    PORT
      LAYER M1 ;
        POLYGON 0.1950 0.1260 0.1950 0.0180 0.1830 0.0180 0.1830 0.1140 0.1410 0.1140 0.1410 0.1260 ;
    END
  END Y
  PIN VDD
    DIRECTION INOUT ;
    USE POWER ;
    PORT
      LAYER M1 ;
        RECT -0.0090 0.1380 0.2190 0.1500 ;
    END
  END VDD
  PIN VSS
    DIRECTION INOUT ;
    USE GROUND ;
    PORT
      LAYER M1 ;
        RECT -0.0090 -0.0060 0.2190 0.0060 ;
    END
  END VSS
  OBS
    LAYER M1 ;
      RECT 0.0570 0.0180 0.1530 0.0300 ;
  END
END OAI31x1

MACRO OR2x1
  CLASS CORE ;
  FOREIGN OR2x1 ;
  ORIGIN 0 0 ;
  SIZE 0.21 BY 0.144 ;
  SYMMETRY X Y ;
  SITE coreSite ;
  PIN A
    DIRECTION INPUT ;
    USE SIGNAL ;
    PORT
      LAYER M1 ;
        RECT 0.0150 0.0180 0.0270 0.1260 ;
    END
  END A
  PIN B
    DIRECTION INPUT ;
    USE SIGNAL ;
    PORT
      LAYER M1 ;
        RECT 0.0990 0.0180 0.1110 0.1020 ;
    END
  END B
  PIN Y
    DIRECTION OUTPUT ;
    USE SIGNAL ;
    PORT
      LAYER M1 ;
        RECT 0.1830 0.0180 0.1950 0.1260 ;
    END
  END Y
  PIN VDD
    DIRECTION INOUT ;
    USE POWER ;
    PORT
      LAYER M1 ;
        RECT -0.0090 0.1380 0.2190 0.1500 ;
    END
  END VDD
  PIN VSS
    DIRECTION INOUT ;
    USE GROUND ;
    PORT
      LAYER M1 ;
        RECT -0.0090 -0.0060 0.2190 0.0060 ;
    END
  END VSS
  OBS
    LAYER M1 ;
      POLYGON 0.1530 0.1260 0.1530 0.0660 0.1410 0.0660 0.1410 0.1140 0.0690 0.1140 0.0690 0.0240 0.0570 0.0240 0.0570 0.1260 ;
  END
END OR2x1

MACRO OR3x1
  CLASS CORE ;
  FOREIGN OR3x1 ;
  ORIGIN 0 0 ;
  SIZE 0.252 BY 0.144 ;
  SYMMETRY X Y ;
  SITE coreSite ;
  PIN A
    DIRECTION INPUT ;
    USE SIGNAL ;
    PORT
      LAYER M1 ;
        RECT 0.0150 0.0180 0.0270 0.1260 ;
    END
  END A
  PIN B
    DIRECTION INPUT ;
    USE SIGNAL ;
    PORT
      LAYER M1 ;
        RECT 0.0570 0.0420 0.0690 0.1260 ;
    END
  END B
  PIN C
    DIRECTION INPUT ;
    USE SIGNAL ;
    PORT
      LAYER M1 ;
        RECT 0.0990 0.0420 0.1110 0.1260 ;
    END
  END C
  PIN Y
    DIRECTION OUTPUT ;
    USE SIGNAL ;
    PORT
      LAYER M1 ;
        RECT 0.2250 0.0180 0.2370 0.1260 ;
    END
  END Y
  PIN VDD
    DIRECTION INOUT ;
    USE POWER ;
    PORT
      LAYER M1 ;
        RECT -0.0090 0.1380 0.2610 0.1500 ;
    END
  END VDD
  PIN VSS
    DIRECTION INOUT ;
    USE GROUND ;
    PORT
      LAYER M1 ;
        RECT -0.0090 -0.0060 0.2610 0.0060 ;
    END
  END VSS
  OBS
    LAYER M1 ;
      POLYGON 0.1530 0.1200 0.1530 0.0780 0.1950 0.0780 0.1950 0.0660 0.1530 0.0660 0.1530 0.0180 0.0570 0.0180 0.0570 0.0300 0.1410 0.0300 0.1410 0.1200 ;
  END
END OR3x1

MACRO OR4x1
  CLASS CORE ;
  FOREIGN OR4x1 ;
  ORIGIN 0 0 ;
  SIZE 0.294 BY 0.144 ;
  SYMMETRY X Y ;
  SITE coreSite ;
  PIN A
    DIRECTION INPUT ;
    USE SIGNAL ;
    PORT
      LAYER M1 ;
        RECT 0.0150 0.0180 0.0270 0.1260 ;
    END
  END A
  PIN B
    DIRECTION INPUT ;
    USE SIGNAL ;
    PORT
      LAYER M1 ;
        RECT 0.0570 0.0420 0.0690 0.1260 ;
    END
  END B
  PIN C
    DIRECTION INPUT ;
    USE SIGNAL ;
    PORT
      LAYER M1 ;
        RECT 0.0990 0.0420 0.1110 0.1260 ;
    END
  END C
  PIN D
    DIRECTION INPUT ;
    USE SIGNAL ;
    PORT
      LAYER M1 ;
        RECT 0.1410 0.0420 0.1530 0.1260 ;
    END
  END D
  PIN Y
    DIRECTION OUTPUT ;
    USE SIGNAL ;
    PORT
      LAYER M1 ;
        RECT 0.2670 0.0180 0.2790 0.1260 ;
    END
  END Y
  PIN VDD
    DIRECTION INOUT ;
    USE POWER ;
    PORT
      LAYER M1 ;
        RECT -0.0090 0.1380 0.3030 0.1500 ;
    END
  END VDD
  PIN VSS
    DIRECTION INOUT ;
    USE GROUND ;
    PORT
      LAYER M1 ;
        RECT -0.0090 -0.0060 0.3030 0.0060 ;
    END
  END VSS
  OBS
    LAYER M1 ;
      POLYGON 0.1950 0.1200 0.1950 0.0780 0.2370 0.0780 0.2370 0.0660 0.1950 0.0660 0.1950 0.0180 0.0570 0.0180 0.0570 0.0300 0.1830 0.0300 0.1830 0.1200 ;
  END
END OR4x1

MACRO XNOR2x1
  CLASS CORE ;
  FOREIGN XNOR2x1 ;
  ORIGIN 0 0 ;
  SIZE 0.378 BY 0.144 ;
  SYMMETRY X Y ;
  SITE coreSite ;
  PIN A
    DIRECTION INPUT ;
    USE SIGNAL ;
    PORT
      LAYER M1 ;
        POLYGON 0.0270 0.1260 0.0270 0.0660 0.1320 0.0660 0.1320 0.0540 0.0270 0.0540 0.0270 0.0180 0.0150 0.0180 0.0150 0.1260 ;
    END
  END A
  PIN B
    DIRECTION INPUT ;
    USE SIGNAL ;
    PORT
      LAYER M1 ;
        POLYGON 0.3630 0.1260 0.3630 0.0180 0.2460 0.0180 0.2460 0.0300 0.3510 0.0300 0.3510 0.1140 0.1620 0.1140 0.1620 0.1260 ;
    END
  END B
  PIN Y
    DIRECTION OUTPUT ;
    USE SIGNAL ;
    PORT
      LAYER M1 ;
        POLYGON 0.1320 0.1260 0.1320 0.1020 0.1950 0.1020 0.1950 0.0900 0.1200 0.0900 0.1200 0.1260 ;
    END
  END Y
  PIN VDD
    DIRECTION INOUT ;
    USE POWER ;
    PORT
      LAYER M1 ;
        RECT -0.0090 0.1380 0.3870 0.1500 ;
    END
  END VDD
  PIN VSS
    DIRECTION INOUT ;
    USE GROUND ;
    PORT
      LAYER M1 ;
        RECT -0.0090 -0.0060 0.3870 0.0060 ;
    END
  END VSS
  OBS
    LAYER M1 ;
      POLYGON 0.3210 0.1020 0.3210 0.0900 0.2370 0.0900 0.2370 0.0420 0.1620 0.0420 0.1620 0.0540 0.2250 0.0540 0.2250 0.1020 ;
      RECT 0.0570 0.0180 0.2160 0.0300 ;
  END
  PROPERTY stopLevel 0 ;
  PROPERTY startLevel 0 ;
  PROPERTY snapMode "orthogonal" ;
  PROPERTY segSnapMode "orthogonal" ;
  PROPERTY pathCL "yes" ;
  PROPERTY lppVisibilityMode "donotCheckValidity" ;
  PROPERTY instanceDrawingMode "BBox" ;
  PROPERTY autoZoomScale 90 ;
  PROPERTY gridSpacing 1 ;
  PROPERTY xSnapSpacing 0.001 ;
  PROPERTY autoZoomMode "Pan" ;
  PROPERTY mergeScope "pcells" ;
  PROPERTY gridMultiple 5 ;
  PROPERTY arrayDisplay "Full" ;
  PROPERTY scrollPercent 25 ;
  PROPERTY displayResolution "Medium" ;
  PROPERTY instLabel "master" ;
  PROPERTY ySnapSpacing 0.001 ;
  PROPERTY filterSize 6 ;
  PROPERTY dimmingIntensity 50 ;
  PROPERTY filterSizeDrawingStyle "empty" ;
  PROPERTY dimmingScope "none" ;
END XNOR2x1

MACRO XNOR3x1
  CLASS CORE ;
  FOREIGN XNOR3x1 ;
  ORIGIN 0 0 ;
  SIZE 0.63 BY 0.144 ;
  SYMMETRY X Y ;
  SITE coreSite ;
  PIN A
    DIRECTION INPUT ;
    USE SIGNAL ;
    PORT
      LAYER M1 ;
        POLYGON 0.0480 0.1260 0.0480 0.0540 0.0900 0.0540 0.0900 0.0420 0.0360 0.0420 0.0360 0.1260 ;
    END
  END A
  PIN B
    DIRECTION INPUT ;
    USE SIGNAL ;
    PORT
      LAYER M1 ;
        POLYGON 0.3420 0.1020 0.3420 0.0540 0.3840 0.0540 0.3840 0.0420 0.3300 0.0420 0.3300 0.1020 ;
    END
  END B
  PIN C
    DIRECTION INPUT ;
    USE SIGNAL ;
    PORT
      LAYER M1 ;
        POLYGON 0.6150 0.1260 0.6150 0.0180 0.4980 0.0180 0.4980 0.0300 0.6030 0.0300 0.6030 0.1140 0.4140 0.1140 0.4140 0.1260 ;
    END
  END C
  PIN Y
    DIRECTION OUTPUT ;
    USE SIGNAL ;
    PORT
      LAYER M1 ;
        POLYGON 0.0900 0.1260 0.0900 0.1020 0.1530 0.1020 0.1530 0.0900 0.0780 0.0900 0.0780 0.1260 ;
    END
  END Y
  PIN VDD
    DIRECTION INOUT ;
    USE POWER ;
    PORT
      LAYER M1 ;
        RECT -0.0090 0.1380 0.6390 0.1500 ;
    END
  END VDD
  PIN VSS
    DIRECTION INOUT ;
    USE GROUND ;
    PORT
      LAYER M1 ;
        RECT -0.0090 -0.0060 0.6390 0.0060 ;
    END
  END VSS
  OBS
    LAYER M1 ;
      POLYGON 0.3840 0.1260 0.3840 0.1020 0.4470 0.1020 0.4470 0.0900 0.3720 0.0900 0.3720 0.1140 0.1200 0.1140 0.1200 0.1260 ;
      POLYGON 0.5720 0.1020 0.5720 0.0900 0.4890 0.0900 0.4890 0.0420 0.4140 0.0420 0.4140 0.0540 0.4770 0.0540 0.4770 0.1020 ;
      POLYGON 0.2790 0.1020 0.2790 0.0900 0.1950 0.0900 0.1950 0.0420 0.1200 0.0420 0.1200 0.0540 0.1830 0.0540 0.1830 0.1020 ;
      RECT 0.3090 0.0180 0.4680 0.0300 ;
      RECT 0.2040 0.0180 0.2580 0.0300 ;
      RECT 0.0150 0.0180 0.1740 0.0300 ;
  END
END XNOR3x1

MACRO XOR2x1
  CLASS CORE ;
  FOREIGN XOR2x1 ;
  ORIGIN 0 0 ;
  SIZE 0.378 BY 0.144 ;
  SYMMETRY X Y ;
  SITE coreSite ;
  PIN A
    DIRECTION INPUT ;
    USE SIGNAL ;
    PORT
      LAYER M1 ;
        POLYGON 0.0270 0.1260 0.0270 0.0660 0.1320 0.0660 0.1320 0.0540 0.0270 0.0540 0.0270 0.0180 0.0150 0.0180 0.0150 0.1260 ;
    END
  END A
  PIN B
    DIRECTION INPUT ;
    USE SIGNAL ;
    PORT
      LAYER M1 ;
        POLYGON 0.3630 0.1260 0.3630 0.0180 0.3510 0.0180 0.3510 0.0780 0.2370 0.0780 0.2370 0.0540 0.1620 0.0540 0.1620 0.0660 0.2250 0.0660 0.2250 0.0900 0.3510 0.0900 0.3510 0.1260 ;
    END
  END B
  PIN Y
    DIRECTION OUTPUT ;
    USE SIGNAL ;
    PORT
      LAYER M1 ;
        POLYGON 0.1320 0.1260 0.1320 0.1020 0.1950 0.1020 0.1950 0.0900 0.1200 0.0900 0.1200 0.1260 ;
    END
  END Y
  PIN VDD
    DIRECTION INOUT ;
    USE POWER ;
    PORT
      LAYER M1 ;
        RECT -0.0090 0.1380 0.3870 0.1500 ;
    END
  END VDD
  PIN VSS
    DIRECTION INOUT ;
    USE GROUND ;
    PORT
      LAYER M1 ;
        RECT -0.0090 -0.0060 0.3870 0.0060 ;
    END
  END VSS
  OBS
    LAYER M1 ;
      RECT 0.1620 0.1140 0.3210 0.1260 ;
      RECT 0.2460 0.0180 0.3210 0.0300 ;
      RECT 0.0570 0.0180 0.2160 0.0300 ;
  END
  PROPERTY stopLevel 0 ;
  PROPERTY startLevel 0 ;
  PROPERTY snapMode "orthogonal" ;
  PROPERTY segSnapMode "orthogonal" ;
  PROPERTY pathCL "yes" ;
  PROPERTY lppVisibilityMode "donotCheckValidity" ;
  PROPERTY instanceDrawingMode "BBox" ;
  PROPERTY autoZoomScale 90 ;
  PROPERTY gridSpacing 1 ;
  PROPERTY xSnapSpacing 0.001 ;
  PROPERTY autoZoomMode "Pan" ;
  PROPERTY mergeScope "pcells" ;
  PROPERTY gridMultiple 5 ;
  PROPERTY arrayDisplay "Full" ;
  PROPERTY scrollPercent 25 ;
  PROPERTY displayResolution "Medium" ;
  PROPERTY instLabel "master" ;
  PROPERTY ySnapSpacing 0.001 ;
  PROPERTY filterSize 6 ;
  PROPERTY dimmingIntensity 50 ;
  PROPERTY filterSizeDrawingStyle "empty" ;
  PROPERTY dimmingScope "none" ;
END XOR2x1

MACRO XOR3x1
  CLASS CORE ;
  FOREIGN XOR3x1 ;
  ORIGIN 0 0 ;
  SIZE 0.63 BY 0.144 ;
  SYMMETRY X Y ;
  SITE coreSite ;
  PIN A
    DIRECTION INPUT ;
    USE SIGNAL ;
    PORT
      LAYER M1 ;
        POLYGON 0.0480 0.1260 0.0480 0.0540 0.0900 0.0540 0.0900 0.0420 0.0360 0.0420 0.0360 0.1260 ;
    END
  END A
  PIN B
    DIRECTION INPUT ;
    USE SIGNAL ;
    PORT
      LAYER M1 ;
        POLYGON 0.3630 0.1020 0.3630 0.0540 0.3840 0.0540 0.3840 0.0420 0.3300 0.0420 0.3300 0.0540 0.3510 0.0540 0.3510 0.1020 ;
    END
  END B
  PIN C
    DIRECTION INPUT ;
    USE SIGNAL ;
    PORT
      LAYER M1 ;
        POLYGON 0.6150 0.1260 0.6150 0.0180 0.6030 0.0180 0.6030 0.0780 0.4890 0.0780 0.4890 0.0540 0.4140 0.0540 0.4140 0.0660 0.4770 0.0660 0.4770 0.0900 0.6030 0.0900 0.6030 0.1260 ;
    END
  END C
  PIN Y
    DIRECTION OUTPUT ;
    USE SIGNAL ;
    PORT
      LAYER M1 ;
        POLYGON 0.0900 0.1260 0.0900 0.1020 0.1530 0.1020 0.1530 0.0900 0.0780 0.0900 0.0780 0.1260 ;
    END
  END Y
  PIN VDD
    DIRECTION INOUT ;
    USE POWER ;
    PORT
      LAYER M1 ;
        RECT -0.0090 0.1380 0.6390 0.1500 ;
    END
  END VDD
  PIN VSS
    DIRECTION INOUT ;
    USE GROUND ;
    PORT
      LAYER M1 ;
        RECT -0.0090 -0.0060 0.6390 0.0060 ;
    END
  END VSS
  OBS
    LAYER M1 ;
      RECT 0.4140 0.1140 0.5730 0.1260 ;
      POLYGON 0.3950 0.1260 0.3950 0.1020 0.4470 0.1020 0.4470 0.0900 0.3830 0.0900 0.3830 0.1140 0.3210 0.1140 0.3210 0.0900 0.1950 0.0900 0.1950 0.0660 0.1200 0.0660 0.1200 0.0780 0.1830 0.0780 0.1830 0.1020 0.3090 0.1020 0.3090 0.1260 ;
      RECT 0.1200 0.1140 0.2790 0.1260 ;
      RECT 0.4980 0.0180 0.5730 0.0300 ;
      RECT 0.3090 0.0180 0.4680 0.0300 ;
      RECT 0.2040 0.0180 0.2790 0.0300 ;
      RECT 0.0150 0.0180 0.1740 0.0300 ;
  END
  PROPERTY stopLevel 0 ;
  PROPERTY startLevel 0 ;
  PROPERTY snapMode "orthogonal" ;
  PROPERTY segSnapMode "orthogonal" ;
  PROPERTY pathCL "yes" ;
  PROPERTY lppVisibilityMode "donotCheckValidity" ;
  PROPERTY instanceDrawingMode "BBox" ;
  PROPERTY autoZoomScale 90 ;
  PROPERTY gridSpacing 1 ;
  PROPERTY xSnapSpacing 0.001 ;
  PROPERTY autoZoomMode "Pan" ;
  PROPERTY mergeScope "pcells" ;
  PROPERTY gridMultiple 5 ;
  PROPERTY arrayDisplay "Full" ;
  PROPERTY scrollPercent 25 ;
  PROPERTY displayResolution "Medium" ;
  PROPERTY instLabel "master" ;
  PROPERTY ySnapSpacing 0.001 ;
  PROPERTY filterSize 6 ;
  PROPERTY dimmingIntensity 50 ;
  PROPERTY filterSizeDrawingStyle "empty" ;
  PROPERTY dimmingScope "none" ;
END XOR3x1

END LIBRARY
